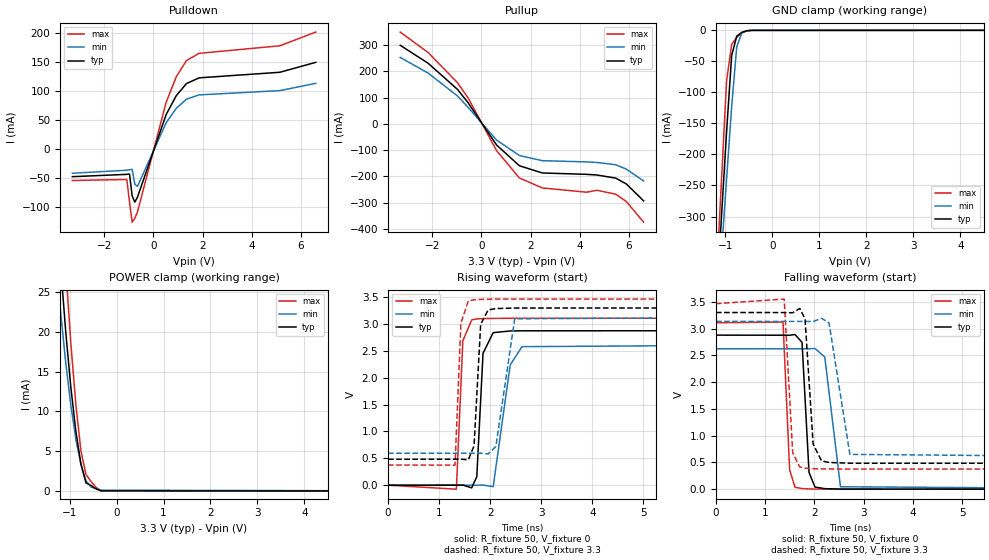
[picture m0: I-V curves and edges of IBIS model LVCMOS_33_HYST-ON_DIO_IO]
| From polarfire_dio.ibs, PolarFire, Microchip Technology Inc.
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|   Model LVCMOS_33_HYST-ON_DIO_IO
[Model]   LVCMOS_33_HYST-ON_DIO_IO
Model_type   I/O
Polarity   Non-Inverting
Enable   Active-High
Vinl =   0.8
Vinh =   2.0
Vmeas =   1.65
Cref =   0
Rref =   1M
|   typ   min   max
C_comp   5.210e-12   5.210e-12   5.520e-12
[Temperature Range]  25C   100C   -40C
[Voltage Range]  3.3   3.135   3.465
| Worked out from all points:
|   slope of the pulldown table from 0 to 0.495 V, typ, clamps not added: 8.62 ohm
|   slope of the pullup table from 0 to 0.495 V, typ, clamps not added: 7.48 ohm
|   GND clamp passes 1 mA (typ) near -0.56 V on its own axis
|   POWER clamp passes 1 mA (typ) near -0.65 V on its own axis
|   rising waveform, R_fixture 50, V_fixture 0: 20-80 % time 83.9ps typ, 115ps min, 62.2ps max; typ from 0 V to 2.88 V
|   rising waveform, R_fixture 50, V_fixture 3.3: 20-80 % time 82.6ps typ, 117ps min, 56.7ps max; typ from 0.483 V to 3.3 V
|   falling waveform, R_fixture 50, V_fixture 0: 20-80 % time 81.5ps typ, 112ps min, 62ps max; typ from 2.88 V to 0 V
|   falling waveform, R_fixture 50, V_fixture 3.3: 20-80 % time 106ps typ, 144ps min, 77.9ps max; typ from 3.3 V to 0.483 V
[GND Clamp]
| Voltage   I(typ)   I(min)   I(max)
-3.3V     -3.117A    -2.775A    -3.571A
-1.408V   -710mA     -709mA     -726.1mA
-1.083V   -300.1mA   -357.4mA   -241.4mA
-974.5mV  -163.4mA   -240mA     -81.84mA
-866.2mV  -40.57mA   -122.6mA   -22.65mA
-758mV    -9.307mA   -26.47mA   -11.46mA
-649.7mV  -3.312mA   -3.932mA   -4.242mA
-541.4mV  -660.8uA   -670.6uA   -884.8uA
-433.1mV  -42.49uA   -60.22uA   -57.85uA
6.6V      0A         0A         0A
[POWER Clamp]
| Voltage   I(typ)   I(min)   I(max)
-3.3V     276.9mA    224mA      333.7mA
-1.299V   37.66mA    29.74mA    51.11mA
-1.191V   28.36mA    22.59mA    39.07mA
-1.083V   20.16mA    16.24mA    28.21mA
-974.5mV  13.17mA    10.86mA    18.75mA
-866.2mV  7.523mA    6.52mA     10.91mA
-758mV    3.401mA    3.308mA    5.047mA
-649.7mV  998.1uA    1.291mA    2.065mA
-541.4mV  687.8uA    491.9uA    1.172mA
-433.1mV  241.5uA    288uA      436.1uA
-324.8mV  6.892uA    96.65uA    11.4uA
6.6V      0A         0A         0A
[Pullup]
| Voltage   I(typ)   I(min)   I(max)
-3.3V     299.9mA    253.5mA    350.3mA
-2.166V   231.4mA    194mA      272.3mA
-974.5mV  131.9mA    106.8mA    157.5mA
-541.4mV  80.8mA     63.2mA     99.39mA
618.8mV   -80.62mA   -61.84mA   -102.2mA
1.547V    -159.8mA   -120.7mA   -206.4mA
2.475V    -187.2mA   -140.4mA   -244.4mA
4.275V    -192.5mA   -145.1mA   -260.6mA
4.708V    -195.1mA   -147.2mA   -253.4mA
5.466V    -206.9mA   -156mA     -268.2mA
5.899V    -229.5mA   -172.8mA   -296.7mA
6.6V      -293.9mA   -217.9mA   -375.1mA
[Pulldown]
| Voltage   I(typ)   I(min)   I(max)
-3.3V     -47.51mA   -41.6mA    -54.13mA
-1.083V   -43.53mA   -36.42mA   -52.3mA
-974.5mV  -42.97mA   -35.55mA   -91.23mA
-866.2mV  -80.6mA    -34.99mA   -125.9mA
-758mV    -91.32mA   -60.63mA   -119.2mA
-649.7mV  -82.66mA   -64.24mA   -108.2mA
515.6mV   59.44mA    45.33mA    80.6mA
928.1mV   92.05mA    70.21mA    124.6mA
1.341V    112.8mA    85.88mA    152.5mA
1.856V    122.7mA    93.34mA    164.9mA
5.141V    132.3mA    100.7mA    177.9mA
6.6V      149.4mA    113.2mA    201.5mA
[Ramp]
dV/dt_r   1.72593/83.9062p  1.57401/0.115219n  1.8646/62.166p
dV/dt_f   1.69003/0.105543n  1.52447/0.143802n  1.85329/77.8518p
R_load = 50
[Rising Waveform]
R_fixture = 50
V_fixture = 0
V_fixture_min = 0
V_fixture_max = 0
| Time   V(typ)   V(min)   V(max)
0s        13.15nV    12.79nV    36.26nV
1.337ns   722.6uV    604.3uV    -73.68mV
1.464ns   3.294mV    661.7uV    2.689V
1.637ns   -49.29mV   739.8uV    3.077V
1.737ns   157.8mV    785uV      3.095V
1.859ns   2.455V     2.552mV    3.101V
2.058ns   2.84V      -27.13mV   3.105V
2.391ns   2.871V     2.238V     3.107V
2.621ns   2.874V     2.579V     3.108V
10ns      2.877V     2.623V     3.108V
[Rising Waveform]
R_fixture = 50
V_fixture = 3.3
V_fixture_min = 3.135
V_fixture_max = 3.465
| Time   V(typ)   V(min)   V(max)
0s        483.3mV    594.2mV    376.2mV
1.311ns   484.1mV    594.9mV    373.2mV
1.426ns   484.3mV    594.9mV    3.017V
1.571ns   472.5mV    595mV      3.431V
1.683ns   731.7mV    595.1mV    3.452V
1.813ns   2.995V     595.1mV    3.459V
1.96ns    3.263V     582.7mV    3.462V
2.111ns   3.288V     720.5mV    3.464V
2.479ns   3.298V     3.098V     3.464V
10ns      3.3V       3.135V     3.465V
[Falling Waveform]
R_fixture = 50
V_fixture = 0
V_fixture_min = 0
V_fixture_max = 0
| Time   V(typ)   V(min)   V(max)
0s        2.877V     2.623V     3.108V
1.362ns   2.876V     2.623V     3.122V
1.497ns   2.875V     2.623V     359.4mV
1.606ns   2.889V     2.623V     36.05mV
1.749ns   2.742V     2.623V     11.66mV
1.891ns   313mV      2.622V     4.403mV
2.011ns   39.38mV    2.628V     1.913mV
2.211ns   9.397mV    2.469V     852.3uV
2.53ns    1.347mV    45.15mV    817.4uV
10ns      130.8nV    260.3nV    53.88nV
[Falling Waveform]
R_fixture = 50
V_fixture = 3.3
V_fixture_min = 3.135
V_fixture_max = 3.465
| Time   V(typ)   V(min)   V(max)
0s        3.3V       3.135V     3.465V
1.386ns   3.299V     3.134V     3.551V
1.559ns   3.295V     3.134V     681.1mV
1.703ns   3.376V     3.134V     413.5mV
1.81ns    3.181V     3.134V     392.6mV
1.974ns   843.3mV    3.131V     381.8mV
2.146ns   527.7mV    3.192V     377.9mV
2.298ns   498.9mV    3.105V     376.8mV
2.721ns   484.6mV    649.5mV    376.3mV
10ns      483.3mV    594.2mV    376.2mV
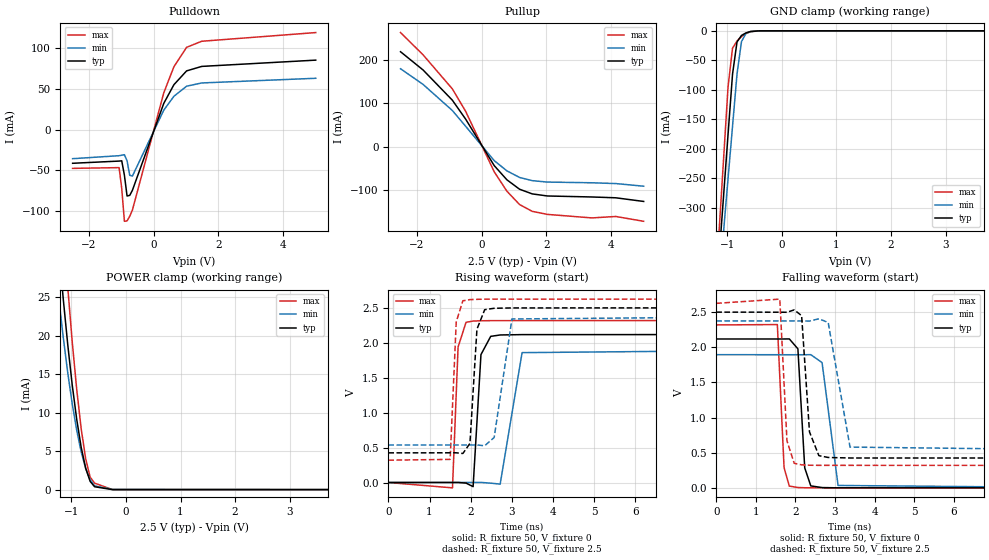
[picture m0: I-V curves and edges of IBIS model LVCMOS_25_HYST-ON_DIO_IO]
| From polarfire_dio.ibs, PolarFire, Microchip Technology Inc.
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|   Model LVCMOS_25_HYST-ON_DIO_IO
[Model]   LVCMOS_25_HYST-ON_DIO_IO
Model_type   I/O
Polarity   Non-Inverting
Enable   Active-High
Vinl =   0.7
Vinh =   1.7
Vmeas =   1.25
Cref =   0
Rref =   1M
|   typ   min   max
C_comp   5.210e-12   5.210e-12   5.520e-12
[Temperature Range]  25C   100C   -40C
[Voltage Range]  2.5   2.375   2.625
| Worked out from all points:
|   slope of the pulldown table from 0 to 0.375 V, typ, clamps not added: 9.99 ohm
|   slope of the pullup table from 0 to 0.375 V, typ, clamps not added: 9 ohm
|   GND clamp passes 1 mA (typ) near -0.56 V on its own axis
|   POWER clamp passes 1 mA (typ) near -0.65 V on its own axis
|   rising waveform, R_fixture 50, V_fixture 0: 20-80 % time 106ps typ, 156ps min, 74.6ps max; typ from 0 V to 2.12 V
|   rising waveform, R_fixture 50, V_fixture 2.5: 20-80 % time 120ps typ, 167ps min, 75.2ps max; typ from 0.425 V to 2.5 V
|   falling waveform, R_fixture 50, V_fixture 0: 20-80 % time 111ps typ, 160ps min, 76.3ps max; typ from 2.12 V to 0 V
|   falling waveform, R_fixture 50, V_fixture 2.5: 20-80 % time 142ps typ, 205ps min, 98.3ps max; typ from 2.5 V to 0.425 V
[GND Clamp]
| Voltage   I(typ)   I(min)   I(max)
-2.5V     -2.095A    -1.898A    -2.363A
-1.395V   -693.5mA   -694.8mA   -706.5mA
-1.066V   -279.4mA   -339.6mA   -216.9mA
-984.4mV  -175.8mA   -250.7mA   -94.98mA
-902.3mV  -73.48mA   -161.7mA   -29.46mA
-820.3mV  -18.91mA   -73.29mA   -17.3mA
-738.3mV  -7.793mA   -18.25mA   -9.861mA
-656.2mV  -3.56mA    -4.35mA    -4.565mA
-574.2mV  -1.196mA   -1.212mA   -1.543mA
-410.2mV  -21.32uA   -34.15uA   -26.17uA
5V        0A         0A         0A
[POWER Clamp]
| Voltage   I(typ)   I(min)   I(max)
-2.5V     165mA      130.6mA    202.6mA
-1.23V    31.26mA    24.82mA    42.73mA
-1.148V   24.72mA    19.74mA    34.16mA
-1.066V   18.82mA    15.17mA    26.29mA
-984.4mV  13.6mA     11.15mA    19.21mA
-902.3mV  9.142mA    7.719mA    13.04mA
-820.3mV  5.508mA    4.906mA    7.92mA
-738.3mV  2.791mA    2.758mA    4.018mA
-656.2mV  1.072mA    1.3mA      1.627mA
-574.2mV  370.7uA    485.9uA    841.5uA
-246.1mV  347.3nA    25.17uA    169.7nA
5V        0A         0A         0A
[Pullup]
| Voltage   I(typ)   I(min)   I(max)
-2.5V     219mA      179.8mA    263.1mA
-1.805V   177mA      143.8mA    211.9mA
-902.3mV  107.5mA    83.69mA    133.5mA
-492.2mV  63.92mA    47.44mA    81.89mA
390.6mV   -43.25mA   -31.76mA   -57.52mA
781.2mV   -75.89mA   -55.27mA   -102.1mA
1.172V    -97.57mA   -70.44mA   -132.8mA
1.562V    -108.3mA   -77.78mA   -148.5mA
2.031V    -113.1mA   -81.1mA    -155.5mA
3.402V    -115.4mA   -82.71mA   -163.6mA
4.141V    -117.3mA   -84.56mA   -160.3mA
5V        -125.7mA   -90.6mA    -171.4mA
[Pulldown]
| Voltage   I(typ)   I(min)   I(max)
-2.5V     -41.56mA   -35.9mA    -47.82mA
-1.066V   -38.84mA   -32.22mA   -46.91mA
-984.4mV  -38.52mA   -31.65mA   -72.62mA
-902.3mV  -56.23mA   -30.99mA   -113mA
-820.3mV  -81.83mA   -38.53mA   -112.5mA
-738.3mV  -81.09mA   -56.31mA   -106.9mA
-656.2mV  -74.9mA    -57.36mA   -99.27mA
312.5mV   32.26mA    23.92mA    45.26mA
625mV     55.23mA    40.94mA    77.37mA
1.016V    72.21mA    53.35mA    101.2mA
1.484V    77.74mA    57.36mA    108.7mA
5V        85.46mA    63.12mA    119.4mA
[Ramp]
dV/dt_r   1.27102/0.106207n  1.137/0.156314n  1.39063/74.598p
dV/dt_f   1.24529/0.142353n  1.10313/0.204769n  1.38324/98.2736p
R_load = 50
[Rising Waveform]
R_fixture = 50
V_fixture = 0
V_fixture_min = 0
V_fixture_max = 0
| Time   V(typ)   V(min)   V(max)
0s        3.055nV    9.243nV    3.186nV
1.559ns   476.4uV    514.2uV    -76.6mV
1.695ns   733.1uV    559uV      1.94V
1.888ns   -8.122mV   622.7uV    2.293V
2.06ns    -59.37mV   679.4uV    2.311V
2.251ns   1.831V     1.472mV    2.315V
2.488ns   2.092V     -9.262mV   2.317V
2.718ns   2.112V     -23.39mV   2.317V
3.251ns   2.117V     1.859V     2.318V
10ns      2.118V     1.895V     2.318V
[Rising Waveform]
R_fixture = 50
V_fixture = 2.5
V_fixture_min = 2.375
V_fixture_max = 2.625
| Time   V(typ)   V(min)   V(max)
0s        424.5mV    536.5mV    319.6mV
1.502ns   425.2mV    537mV      331mV
1.65ns    425.3mV    537.1mV    2.299V
1.811ns   415.2mV    537.2mV    2.601V
1.983ns   560.2mV    537.2mV    2.618V
2.153ns   2.194V     537.3mV    2.622V
2.342ns   2.474V     526.4mV    2.624V
2.572ns   2.494V     645.1mV    2.625V
3.004ns   2.499V     2.341V     2.625V
10ns      2.5V       2.375V     2.625V
[Falling Waveform]
R_fixture = 50
V_fixture = 0
V_fixture_min = 0
V_fixture_max = 0
| Time   V(typ)   V(min)   V(max)
0s        2.118V     1.895V     2.318V
1.543ns   2.118V     1.894V     2.323V
1.713ns   2.118V     1.894V     286.4mV
1.845ns   2.119V     1.894V     25.28mV
2.062ns   1.978V     1.894V     5.01mV
2.235ns   283.7mV    1.894V     1.642mV
2.388ns   28.06mV    1.895V     915uV
2.673ns   4.176mV    1.782V     880.8uV
3.077ns   393.1uV    34.37mV    832.2uV
10ns      212.4nV    437.4nV    100.6nV
[Falling Waveform]
R_fixture = 50
V_fixture = 2.5
V_fixture_min = 2.375
V_fixture_max = 2.625
| Time   V(typ)   V(min)   V(max)
0s        2.5V       2.375V     2.625V
1.605ns   2.499V     2.375V     2.685V
1.786ns   2.498V     2.375V     668mV
1.969ns   2.532V     2.375V     349.9mV
2.156ns   2.45V      2.374V     327.3mV
2.355ns   796.4mV    2.373V     321.9mV
2.592ns   458.2mV    2.405V     320.4mV
2.827ns   432.4mV    2.353V     320.4mV
3.379ns   424.9mV    580mV      320.3mV
10ns      424.5mV    536.5mV    319.6mV
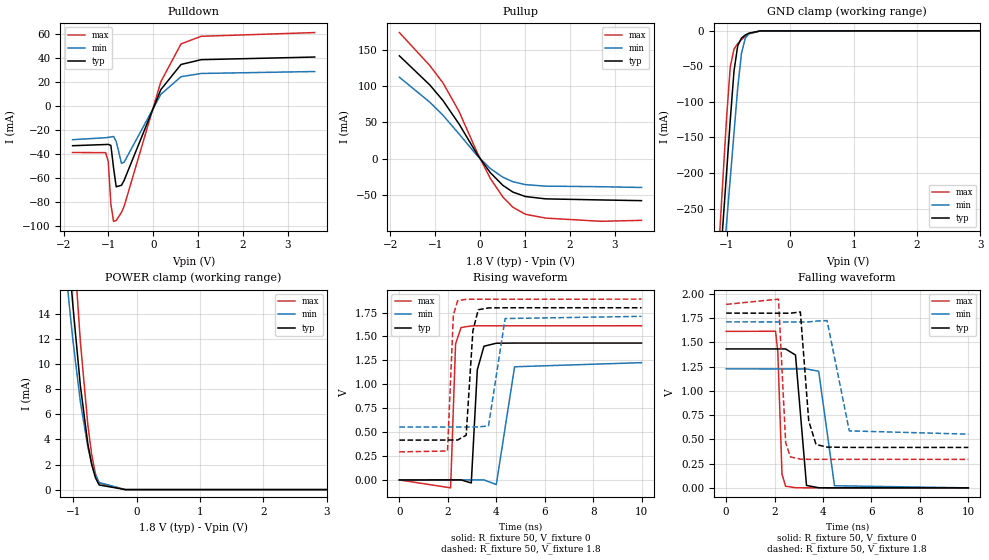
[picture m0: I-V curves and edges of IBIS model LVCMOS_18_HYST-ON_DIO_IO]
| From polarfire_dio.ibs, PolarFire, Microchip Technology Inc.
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|   Model LVCMOS_18_HYST-ON_DIO_IO
[Model]   LVCMOS_18_HYST-ON_DIO_IO
Model_type   I/O
Polarity   Non-Inverting
Enable   Active-High
Vinl =   0.63
Vinh =   1.17
Vmeas =   0.9
Cref =   0
Rref =   1M
|   typ   min   max
C_comp   5.210e-12   5.210e-12   5.520e-12
[Temperature Range]  25C   100C   -40C
[Voltage Range]  1.8   1.71   1.89
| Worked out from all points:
|   slope of the pulldown table from 0 to 0.27 V, typ, clamps not added: 13.4 ohm
|   slope of the pullup table from 0 to 0.27 V, typ, clamps not added: 12.3 ohm
|   GND clamp passes 1 mA (typ) near -0.56 V on its own axis
|   POWER clamp passes 1 mA (typ) near -0.65 V on its own axis
|   rising waveform, R_fixture 50, V_fixture 0: 20-80 % time 168ps typ, 272ps min, 104ps max; typ from 0 V to 1.43 V
|   rising waveform, R_fixture 50, V_fixture 1.8: 20-80 % time 204ps typ, 277ps min, 126ps max; typ from 0.416 V to 1.8 V
|   falling waveform, R_fixture 50, V_fixture 0: 20-80 % time 188ps typ, 262ps min, 119ps max; typ from 1.43 V to 0 V
|   falling waveform, R_fixture 50, V_fixture 1.8: 20-80 % time 246ps typ, 393ps min, 155ps max; typ from 1.8 V to 0.416 V
[GND Clamp]
| Voltage   I(typ)   I(min)   I(max)
-1.8V     -1.205A    -1.134A    -1.312A
-1.122V   -349.8mA   -400mA     -300.1mA
-1.063V   -275.3mA   -336.1mA   -212mA
-1.004V   -200.7mA   -272.1mA   -124mA
-945mV    -126mA     -208mA     -50.93mA
-885.9mV  -56.73mA   -143.9mA   -25.77mA
-826.9mV  -20.87mA   -80mA      -17.98mA
-767.8mV  -10.21mA   -31.7mA    -12.3mA
-708.7mV  -5.982mA   -10.49mA   -7.692mA
-649.7mV  -3.311mA   -3.931mA   -4.24mA
-472.5mV  -129.2uA   -153.5uA   -189.6uA
3.6V      0A         0A         0A
[POWER Clamp]
| Voltage   I(typ)   I(min)   I(max)
-1.8V     86.23mA    65.8mA     111.2mA
-1.181V   27.05mA    21.5mA     37.2mA
-1.122V   22.57mA    18.03mA    31.3mA
-1.063V   18.44mA    14.83mA    25.76mA
-1.004V   14.67mA    11.92mA    20.64mA
-885.9mV  8.285mA    7.004mA    11.79mA
-767.8mV  3.63mA     3.384mA    5.147mA
-708.7mV  2.037mA    2.095mA    2.833mA
-649.7mV  965.6uA    1.163mA    1.28mA
-590.6mV  371.5uA    565.4uA    529.2uA
-177.2mV  893pA      1.382uA    111.2nA
3.6V      0A         0A         0A
[Pullup]
| Voltage   I(typ)   I(min)   I(max)
-1.8V     141.7mA    112.3mA    173.7mA
-1.122V   101.7mA    77.94mA    128.4mA
-826.9mV  80.12mA    59.94mA    104.4mA
-472.5mV  48.24mA    34.49mA    65.57mA
-59.06mV  5.582mA    3.989mA    7.857mA
225mV     -18.79mA   -13.15mA   -26.66mA
506.2mV   -36.4mA    -25.27mA   -52.38mA
731.2mV   -45.74mA   -31.52mA   -66.56mA
1.012V    -51.87mA   -35.5mA    -76.31mA
1.462V    -55.09mA   -37.58mA   -81.53mA
2.686V    -56.56mA   -38.35mA   -85.94mA
3.6V      -57.53mA   -39.42mA   -84.65mA
[Pulldown]
| Voltage   I(typ)   I(min)   I(max)
-1.8V     -33.14mA   -28.12mA   -38.79mA
-1.063V   -32.14mA   -26.5mA    -38.91mA
-1.004V   -32.03mA   -26.19mA   -46.39mA
-945mV    -32.91mA   -25.84mA   -81.99mA
-885.9mV  -51.56mA   -25.43mA   -96.1mA
-826.9mV  -67.35mA   -29.57mA   -95.49mA
-708.7mV  -66.09mA   -47.84mA   -88.63mA
-649.7mV  -61.97mA   -46.84mA   -83.61mA
168.8mV   13.57mA    9.638mA    20.15mA
618.8mV   34.53mA    24.36mA    51.68mA
1.069V    38.53mA    27.03mA    58mA
3.6V      40.73mA    28.66mA    61.11mA
[Ramp]
dV/dt_r   0.85864/0.167888n  0.735429/0.272041n  0.966984/0.10411n
dV/dt_f   0.830138/0.245894n  0.694162/0.392686n  0.957958/0.154706n
R_load = 50
[Rising Waveform]
R_fixture = 50
V_fixture = 0
V_fixture_min = 0
V_fixture_max = 0
| Time   V(typ)   V(min)   V(max)
0s        2.576nV    10nV       1.786nV
2.116ns   391.7uV    616.9uV    -82.64mV
2.321ns   429.7uV    676.7uV    1.422V
2.547ns   412.1uV    742.6uV    1.593V
2.97ns    -31.45mV   865.9uV    1.61V
3.219ns   1.152V     938.5uV    1.611V
3.495ns   1.398V     408.2uV    1.611V
4.003ns   1.429V     -47.81mV   1.611V
4.759ns   1.431V     1.183V     1.611V
10ns      1.431V     1.226V     1.612V
[Rising Waveform]
R_fixture = 50
V_fixture = 1.8
V_fixture_min = 1.71
V_fixture_max = 1.89
| Time   V(typ)   V(min)   V(max)
0s        416.4mV    553.1mV    293.4mV
1.989ns   417.2mV    553.4mV    302.4mV
2.23ns    417.3mV    553.4mV    1.722V
2.404ns   417.5mV    553.4mV    1.873V
2.758ns   466.8mV    553.5mV    1.888V
3.036ns   1.558V     553.5mV    1.889V
3.257ns   1.779V     553.7mV    1.889V
3.682ns   1.798V     565.7mV    1.889V
4.367ns   1.8V       1.687V     1.889V
10ns      1.8V       1.71V      1.89V
[Falling Waveform]
R_fixture = 50
V_fixture = 0
V_fixture_min = 0
V_fixture_max = 0
| Time   V(typ)   V(min)   V(max)
0s        1.431V     1.226V     1.612V
2.039ns   1.431V     1.225V     1.613V
2.133ns   1.431V     1.225V     1.397V
2.305ns   1.431V     1.225V     143.2mV
2.451ns   1.431V     1.225V     17.09mV
2.862ns   1.368V     1.225V     1.249mV
3.317ns   24.81mV    1.225V     426.4uV
3.82ns    1.254mV    1.201V     394.3uV
4.473ns   244.2uV    21.79mV    352.7uV
10ns      358nV      485.8nV    272.1nV
[Falling Waveform]
R_fixture = 50
V_fixture = 1.8
V_fixture_min = 1.71
V_fixture_max = 1.89
| Time   V(typ)   V(min)   V(max)
0s        1.8V       1.71V      1.89V
2.16ns    1.799V     1.709V     1.944V
2.457ns   1.799V     1.709V     464.3mV
2.654ns   1.799V     1.709V     319.1mV
3.064ns   1.812V     1.709V     295.6mV
3.409ns   689.6mV    1.709V     294mV
3.71ns    446.7mV    1.718V     294mV
4.166ns   419.8mV    1.723V     293.9mV
5.085ns   416.7mV    587mV      293.9mV
10ns      416.4mV    553.1mV    293.4mV
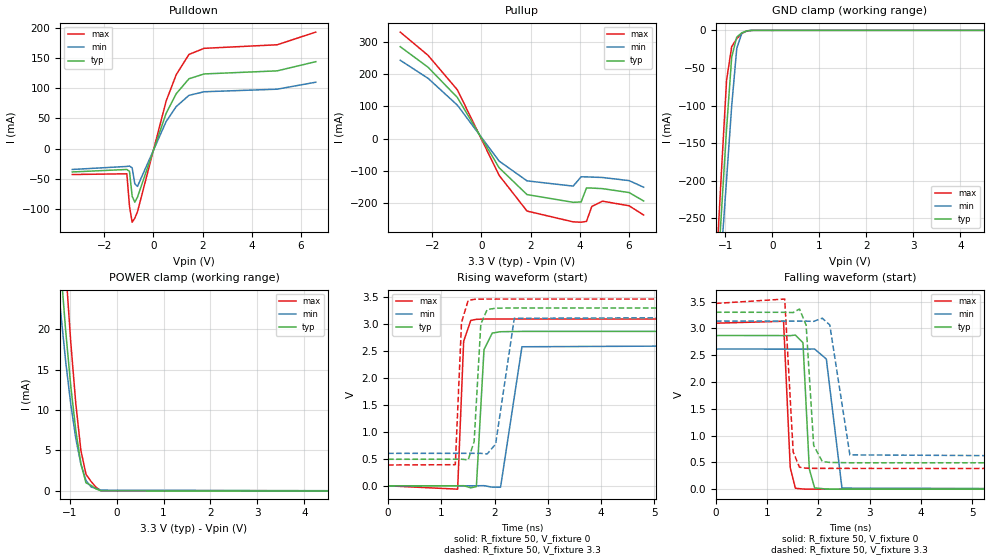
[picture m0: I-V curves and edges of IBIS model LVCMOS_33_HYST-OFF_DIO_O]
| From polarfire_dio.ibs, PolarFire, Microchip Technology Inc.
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|   Model LVCMOS_33_HYST-OFF_DIO_O
[Model]   LVCMOS_33_HYST-OFF_DIO_O
Model_type   Output
Polarity   Non-Inverting
Enable   Active-High
Vmeas =   1.65
Cref =   0
Rref =   1M
|   typ   min   max
C_comp   5.210e-12   5.210e-12   5.520e-12
[Temperature Range]  25C   100C   -40C
[Voltage Range]  3.3   3.135   3.465
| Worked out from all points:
|   slope of the pulldown table from 0 to 0.495 V, typ, clamps not added: 8.78 ohm
|   slope of the pullup table from 0 to 0.495 V, typ, clamps not added: 7.68 ohm
|   GND clamp passes 1 mA (typ) near -0.56 V on its own axis
|   POWER clamp passes 1 mA (typ) near -0.65 V on its own axis
|   rising waveform, R_fixture 50, V_fixture 0: 20-80 % time 80.9ps typ, 111ps min, 60ps max; typ from 0 V to 2.87 V
|   rising waveform, R_fixture 50, V_fixture 3.3: 20-80 % time 86.3ps typ, 122ps min, 58.7ps max; typ from 0.492 V to 3.3 V
|   falling waveform, R_fixture 50, V_fixture 0: 20-80 % time 76.8ps typ, 101ps min, 59.3ps max; typ from 2.87 V to 0 V
|   falling waveform, R_fixture 50, V_fixture 3.3: 20-80 % time 98.9ps typ, 134ps min, 74.1ps max; typ from 3.3 V to 0.492 V
[GND Clamp]
| Voltage   I(typ)   I(min)   I(max)
-3.3V     -2.496A    -2.286A    -2.76A
-1.191V   -350.6mA   -391.8mA   -312.3mA
-1.083V   -240.9mA   -295mA     -187.1mA
-974.5mV  -131mA     -198.1mA   -66.4mA
-866.2mV  -35.74mA   -101.1mA   -21.82mA
-758mV    -9.042mA   -24.11mA   -11.13mA
-649.7mV  -3.236mA   -3.831mA   -4.137mA
-541.4mV  -641.9uA   -649.7uA   -862.7uA
-433.1mV  -39.78uA   -56.66uA   -54.99uA
6.6V      0A         0A         0A
[POWER Clamp]
| Voltage   I(typ)   I(min)   I(max)
-3.3V     267.5mA    217.4mA    320.4mA
-1.299V   36.87mA    29.24mA    49.76mA
-1.191V   27.83mA    22.24mA    38.13mA
-1.083V   19.83mA    16.03mA    27.61mA
-974.5mV  12.99mA    10.74mA    18.4mA
-866.2mV  7.439mA    6.459mA    10.74mA
-758mV    3.374mA    3.284mA    4.987mA
-649.7mV  993.1uA    1.284mA    2.053mA
-541.4mV  687.6uA    490.7uA    1.166mA
-433.1mV  238.1uA    287.8uA    429.7uA
-324.8mV  6.781uA    96.53uA    11.45uA
6.6V      0A         0A         0A
[Pullup]
| Voltage   I(typ)   I(min)   I(max)
-3.3V     284.3mA    242.4mA    329.4mA
-2.166V   220.6mA    186.4mA    257.3mA
-974.5mV  127.1mA    103.5mA    150.7mA
721.9mV   -89.81mA   -69.17mA   -113.3mA
1.856V    -172.7mA   -130.3mA   -223.6mA
3.733V    -196.6mA   -146.5mA   -257mA
4.058V    -195.4mA   -117.7mA   -258mA
4.275V    -152.1mA   -118mA     -255.6mA
4.491V    -152.6mA   -118.6mA   -209.5mA
4.924V    -154.3mA   -119.9mA   -193.1mA
6.007V    -166.4mA   -129.5mA   -207.2mA
6.6V      -192.5mA   -150mA     -235.9mA
[Pulldown]
| Voltage   I(typ)   I(min)   I(max)
-3.3V     -38.79mA   -34.69mA   -43.07mA
-1.083V   -34.72mA   -29.68mA   -41.85mA
-974.5mV  -37.99mA   -29.03mA   -95.72mA
-866.2mV  -79.08mA   -31.94mA   -122mA
-758mV    -88.84mA   -58.53mA   -115.2mA
-649.7mV  -80.51mA   -62.77mA   -104.7mA
515.6mV   58.35mA    44.7mA     78.62mA
928.1mV   90.9mA     69.54mA    122.5mA
1.444V    115.5mA    88.04mA    155.8mA
2.062V    123.5mA    94.01mA    165.9mA
5.032V    128.6mA    98.25mA    171.8mA
6.6V      143.8mA    109.8mA    192.8mA
[Ramp]
dV/dt_r   1.71943/80.9268p  1.56835/0.110667n  1.85733/59.955p
dV/dt_f   1.68455/98.9451p  1.51988/0.134109n  1.84694/74.1429p
R_load = 50
[Rising Waveform]
R_fixture = 50
V_fixture = 0
V_fixture_min = 0
V_fixture_max = 0
| Time   V(typ)   V(min)   V(max)
0s        12.92nV    12.54nV    35.54nV
1.307ns   827.3uV    645.9uV    -62.18mV
1.42ns    2.54mV     701.8uV    2.682V
1.554ns   -37.98mV   768uV      3.069V
1.659ns   -14.36mV   819.9uV    3.089V
1.802ns   2.527V     2.682mV    3.094V
1.956ns   2.833V     -24.83mV   3.095V
2.113ns   2.859V     -26.26mV   3.095V
2.515ns   2.865V     2.58V      3.095V
10ns      2.866V     2.614V     3.096V
[Rising Waveform]
R_fixture = 50
V_fixture = 3.3
V_fixture_min = 3.135
V_fixture_max = 3.465
| Time   V(typ)   V(min)   V(max)
0s        492.4mV    601.9mV    386.8mV
1.263ns   493.1mV    602.6mV    391.9mV
1.38ns    493.3mV    602.6mV    3.031V
1.505ns   481.7mV    602.7mV    3.441V
1.617ns   822.1mV    602.8mV    3.46V
1.742ns   3V         602.7mV    3.464V
1.861ns   3.269V     590.2mV    3.465V
2.02ns    3.295V     773.3mV    3.465V
2.371ns   3.3V       3.108V     3.465V
10ns      3.3V       3.135V     3.465V
[Falling Waveform]
R_fixture = 50
V_fixture = 0
V_fixture_min = 0
V_fixture_max = 0
| Time   V(typ)   V(min)   V(max)
0s        2.866V     2.614V     3.096V
1.318ns   2.865V     2.613V     3.132V
1.449ns   2.864V     2.613V     398.5mV
1.549ns   2.874V     2.613V     16.9mV
1.697ns   2.732V     2.613V     2.398mV
1.821ns   373.8mV    2.613V     608.7uV
1.924ns   24.47mV    2.614V     212.9uV
2.153ns   1.854mV    2.428V     -25.88uV
2.458ns   372uV      19.15mV    -24.88uV
10ns      10.43nV    38.87nV    39.93nV
[Falling Waveform]
R_fixture = 50
V_fixture = 3.3
V_fixture_min = 3.135
V_fixture_max = 3.465
| Time   V(typ)   V(min)   V(max)
0s        3.3V       3.135V     3.465V
1.341ns   3.299V     3.135V     3.546V
1.506ns   3.294V     3.134V     694.2mV
1.629ns   3.361V     3.134V     409mV
1.759ns   3.059V     3.134V     391.7mV
1.906ns   817mV      3.13V      387.5mV
2.074ns   515.3mV    3.189V     387.3mV
2.22ns    498.3mV    3.063V     387.3mV
2.612ns   492.5mV    639.6mV    387.3mV
10ns      492.4mV    601.9mV    386.8mV
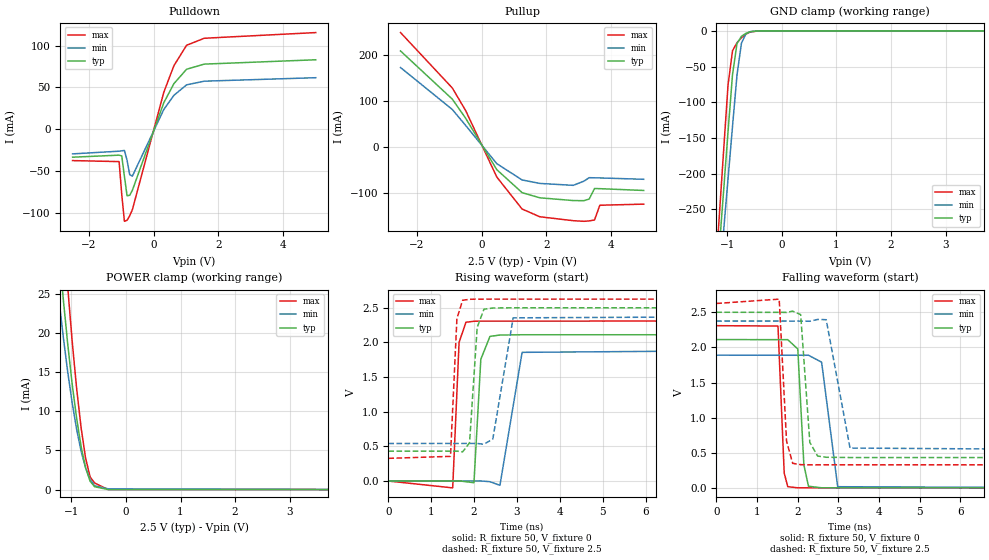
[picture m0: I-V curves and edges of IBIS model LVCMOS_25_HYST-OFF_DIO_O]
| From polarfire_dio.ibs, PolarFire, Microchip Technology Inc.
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|   Model LVCMOS_25_HYST-OFF_DIO_O
[Model]   LVCMOS_25_HYST-OFF_DIO_O
Model_type   Output
Polarity   Non-Inverting
Enable   Active-High
Vmeas =   1.25
Cref =   0
Rref =   1M
|   typ   min   max
C_comp   5.210e-12   5.210e-12   5.520e-12
[Temperature Range]  25C   100C   -40C
[Voltage Range]  2.5   2.375   2.625
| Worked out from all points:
|   slope of the pulldown table from 0 to 0.375 V, typ, clamps not added: 10.2 ohm
|   slope of the pullup table from 0 to 0.375 V, typ, clamps not added: 9.19 ohm
|   GND clamp passes 1 mA (typ) near -0.56 V on its own axis
|   POWER clamp passes 1 mA (typ) near -0.65 V on its own axis
|   rising waveform, R_fixture 50, V_fixture 0: 20-80 % time 102ps typ, 150ps min, 71.4ps max; typ from 0 V to 2.11 V
|   rising waveform, R_fixture 50, V_fixture 2.5: 20-80 % time 122ps typ, 173ps min, 79.5ps max; typ from 0.431 V to 2.5 V
|   falling waveform, R_fixture 50, V_fixture 0: 20-80 % time 100ps typ, 140ps min, 71.1ps max; typ from 2.11 V to 0 V
|   falling waveform, R_fixture 50, V_fixture 2.5: 20-80 % time 132ps typ, 191ps min, 90.9ps max; typ from 2.5 V to 0.431 V
[GND Clamp]
| Voltage   I(typ)   I(min)   I(max)
-2.5V     -1.679A    -1.564A    -1.828A
-1.477V   -639.7mA   -646.8mA   -642.5mA
-1.148V   -307.4mA   -353.7mA   -263mA
-1.066V   -224.2mA   -280.3mA   -168.1mA
-984.4mV  -141mA     -206.9mA   -75.61mA
-902.3mV  -60.93mA   -133.4mA   -27.8mA
-820.3mV  -17.83mA   -61.68mA   -16.76mA
-738.3mV  -7.59mA    -17.01mA   -9.586mA
-656.2mV  -3.478mA   -4.235mA   -4.452mA
-574.2mV  -1.166mA   -1.18mA    -1.507mA
-410.2mV  -20.08uA   -32.05uA   -24.59uA
5V        0A         0A         0A
[POWER Clamp]
| Voltage   I(typ)   I(min)   I(max)
-2.5V     160.3mA    127.5mA    195.9mA
-1.23V    30.66mA    24.43mA    41.69mA
-1.148V   24.29mA    19.45mA    33.39mA
-1.066V   18.52mA    14.97mA    25.75mA
-984.4mV  13.41mA    11.03mA    18.86mA
-902.3mV  9.033mA    7.644mA    12.83mA
-820.3mV  5.454mA    4.866mA    7.812mA
-738.3mV  2.77mA     2.739mA    3.975mA
-656.2mV  1.066mA    1.294mA    1.617mA
-574.2mV  370.6uA    484uA      841.3uA
-328.1mV  7.68uA     101.4uA    7.539uA
5V        0A         0A         0A
[Pullup]
| Voltage   I(typ)   I(min)   I(max)
-2.5V     209mA      172.9mA    249.1mA
-902.3mV  104mA      81.45mA    128.3mA
-492.2mV  62.44mA    46.82mA    79.22mA
468.8mV   -49.63mA   -36.58mA   -65.69mA
1.25V     -99.75mA   -72.09mA   -135.5mA
1.797V    -111mA     -79.67mA   -152.3mA
2.828V    -117mA     -83.84mA   -160.9mA
3.156V    -117.3mA   -74.75mA   -162.2mA
3.32V     -113.7mA   -67.14mA   -161.3mA
3.484V    -90.73mA   -67.41mA   -159.3mA
3.648V    -91.11mA   -67.68mA   -127.2mA
5V        -94.99mA   -70.64mA   -124.8mA
[Pulldown]
| Voltage   I(typ)   I(min)   I(max)
-2.5V     -33.46mA   -29.51mA   -37.53mA
-1.066V   -31.03mA   -26.28mA   -38.76mA
-984.4mV  -31.94mA   -25.85mA   -77.86mA
-902.3mV  -56.28mA   -25.39mA   -110.2mA
-820.3mV  -79.63mA   -37.22mA   -109mA
-738.3mV  -79.02mA   -54.45mA   -103.6mA
-656.2mV  -73.07mA   -56.09mA   -96.24mA
312.5mV   31.72mA    23.62mA    44.19mA
625mV     54.58mA    40.59mA    76.11mA
1.016V    71.81mA    53.14mA    100.5mA
1.562V    77.94mA    57.52mA    108.9mA
5V        83.13mA    61.67mA    115.7mA
[Ramp]
dV/dt_r   1.26639/0.101977n  1.13317/0.150236n  1.38531/71.4107p
dV/dt_f   1.24141/0.131969n  1.10005/0.191455n  1.37859/90.8551p
R_load = 50
[Rising Waveform]
R_fixture = 50
V_fixture = 0
V_fixture_min = 0
V_fixture_max = 0
| Time   V(typ)   V(min)   V(max)
0s        3.015nV    9.048nV    3.118nV
1.501ns   666uV      571.9uV    -98.44mV
1.65ns    2.358mV    628.7uV    2.002V
1.81ns    -9.896mV   689.7uV    2.291V
1.997ns   -23.95mV   760.9uV    2.306V
2.157ns   1.757V     1.214mV    2.308V
2.37ns    2.087V     -9.475mV   2.308V
2.603ns   2.107V     -61.86mV   2.308V
3.12ns    2.111V     1.857V     2.308V
10ns      2.111V     1.889V     2.309V
[Rising Waveform]
R_fixture = 50
V_fixture = 2.5
V_fixture_min = 2.375
V_fixture_max = 2.625
| Time   V(typ)   V(min)   V(max)
0s        431mV      541.6mV    327.3mV
1.449ns   431.8mV    542.2mV    356.2mV
1.599ns   431.9mV    542.3mV    2.344V
1.732ns   420.7mV    542.4mV    2.608V
1.894ns   551.6mV    542.5mV    2.623V
2.072ns   2.216V     542.5mV    2.624V
2.229ns   2.479V     530.9mV    2.625V
2.437ns   2.497V     606.6mV    2.625V
2.912ns   2.5V       2.355V     2.625V
10ns      2.5V       2.375V     2.625V
[Falling Waveform]
R_fixture = 50
V_fixture = 0
V_fixture_min = 0
V_fixture_max = 0
| Time   V(typ)   V(min)   V(max)
0s        2.111V     1.889V     2.309V
1.517ns   2.11V      1.888V     2.304V
1.67ns    2.11V      1.888V     211.3mV
1.757ns   2.11V      1.888V     16.77mV
2.004ns   1.977V     1.888V     958.2uV
2.154ns   326mV      1.888V     152.5uV
2.267ns   22.81mV    1.888V     128.1uV
2.59ns    994.8uV    1.789V     122.8uV
2.985ns   31.17uV    16.38mV    116.2uV
10ns      15.04nV    -20.4nV    37.17nV
[Falling Waveform]
R_fixture = 50
V_fixture = 2.5
V_fixture_min = 2.375
V_fixture_max = 2.625
| Time   V(typ)   V(min)   V(max)
0s        2.5V       2.375V     2.625V
1.547ns   2.499V     2.375V     2.687V
1.727ns   2.498V     2.375V     667mV
1.878ns   2.516V     2.374V     349.4mV
2.075ns   2.466V     2.374V     330.4mV
2.3ns     646.9mV    2.372V     328.2mV
2.492ns   452.9mV    2.398V     328.1mV
2.703ns   435.7mV    2.394V     328.1mV
3.288ns   431.7mV    566.7mV    328.1mV
10ns      431mV      541.6mV    327.4mV
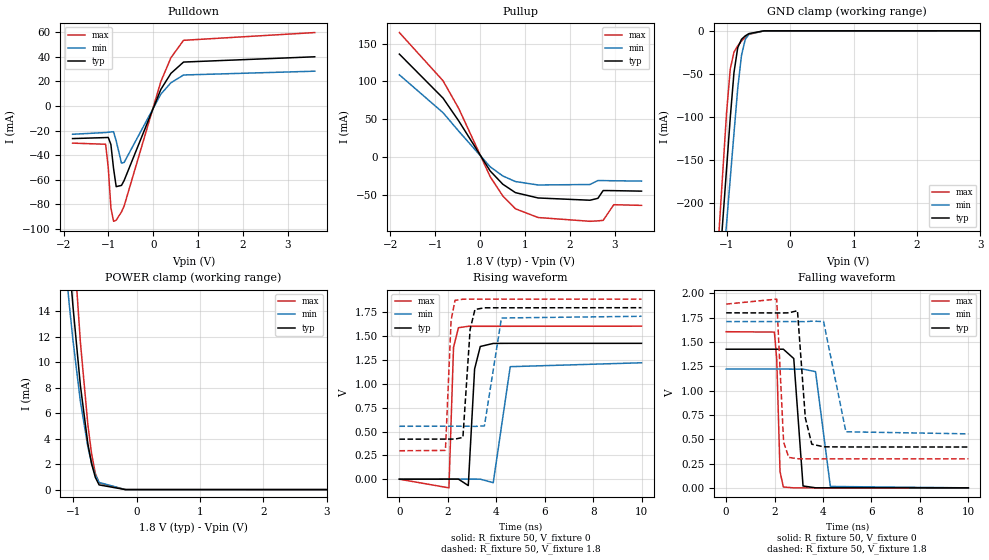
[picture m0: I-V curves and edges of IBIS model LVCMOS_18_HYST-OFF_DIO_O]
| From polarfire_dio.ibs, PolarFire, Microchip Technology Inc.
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|   Model LVCMOS_18_HYST-OFF_DIO_O
[Model]   LVCMOS_18_HYST-OFF_DIO_O
Model_type   Output
Polarity   Non-Inverting
Enable   Active-High
Vmeas =   0.9
Cref =   0
Rref =   1M
|   typ   min   max
C_comp   5.210e-12   5.210e-12   5.520e-12
[Temperature Range]  25C   100C   -40C
[Voltage Range]  1.8   1.71   1.89
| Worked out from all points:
|   slope of the pulldown table from 0 to 0.27 V, typ, clamps not added: 13.6 ohm
|   slope of the pullup table from 0 to 0.27 V, typ, clamps not added: 12.4 ohm
|   GND clamp passes 1 mA (typ) near -0.56 V on its own axis
|   POWER clamp passes 1 mA (typ) near -0.65 V on its own axis
|   rising waveform, R_fixture 50, V_fixture 0: 20-80 % time 158ps typ, 259ps min, 99.8ps max; typ from 0 V to 1.43 V
|   rising waveform, R_fixture 50, V_fixture 1.8: 20-80 % time 201ps typ, 263ps min, 128ps max; typ from 0.42 V to 1.8 V
|   falling waveform, R_fixture 50, V_fixture 0: 20-80 % time 169ps typ, 240ps min, 107ps max; typ from 1.43 V to 0 V
|   falling waveform, R_fixture 50, V_fixture 1.8: 20-80 % time 232ps typ, 367ps min, 142ps max; typ from 1.8 V to 0.42 V
[GND Clamp]
| Voltage   I(typ)   I(min)   I(max)
-1.8V     -967.4mA   -936mA     -1.017A
-1.122V   -280.8mA   -330.2mA   -232.6mA
-1.063V   -220.9mA   -277.4mA   -164.3mA
-1.004V   -161mA     -224.5mA   -96.19mA
-945mV    -101.1mA   -171.6mA   -44.3mA
-885.9mV  -48.29mA   -118.7mA   -24.65mA
-826.9mV  -19.53mA   -66.85mA   -17.42mA
-767.8mV  -9.896mA   -28.51mA   -11.95mA
-708.7mV  -5.838mA   -10.03mA   -7.488mA
-649.7mV  -3.236mA   -3.831mA   -4.137mA
-413.4mV  -21.99uA   -34.81uA   -27.67uA
3.6V      0A         0A         0A
[POWER Clamp]
| Voltage   I(typ)   I(min)   I(max)
-1.8V     84.18mA    64.55mA    108.3mA
-1.181V   26.56mA    21.18mA    36.35mA
-1.122V   22.19mA    17.78mA    30.61mA
-1.063V   18.15mA    14.64mA    25.24mA
-1.004V   14.46mA    11.78mA    20.25mA
-885.9mV  8.189mA    6.938mA    11.61mA
-767.8mV  3.599mA    3.36mA     5.087mA
-708.7mV  2.023mA    2.083mA    2.807mA
-649.7mV  960.8uA    1.157mA    1.272mA
-590.6mV  370.1uA    563.2uA    527.4uA
-177.2mV  3.647uA    1.451uA    394.3nA
3.6V      0A         0A         0A
[Pullup]
| Voltage   I(typ)   I(min)   I(max)
-1.8V     136.1mA    108.7mA    164.6mA
-826.9mV  77.93mA    58.62mA    100.9mA
-472.5mV  47.38mA    33.92mA    63.75mA
225mV     -18.49mA   -13mA      -26.05mA
506.2mV   -36mA      -25.08mA   -51.52mA
787.5mV   -47.14mA   -32.49mA   -68.52mA
1.294V    -54.22mA   -37.03mA   -80.09mA
2.45V     -57.21mA   -36.41mA   -85.08mA
2.627V    -54.71mA   -31.15mA   -84.51mA
2.745V    -44.38mA   -31.25mA   -83.85mA
2.981V    -44.54mA   -31.45mA   -63.12mA
3.6V      -45.17mA   -31.9mA    -64mA
[Pulldown]
| Voltage   I(typ)   I(min)   I(max)
-1.8V     -26.54mA   -23.04mA   -30.22mA
-1.063V   -25.73mA   -21.64mA   -31.16mA
-1.004V   -25.63mA   -21.4mA    -50.06mA
-945mV    -31.3mA    -21.13mA   -82.69mA
-885.9mV  -50.84mA   -20.98mA   -93.72mA
-826.9mV  -65.57mA   -28.4mA    -92.78mA
-708.7mV  -64.56mA   -46.5mA    -86.11mA
-649.7mV  -60.59mA   -45.89mA   -81.3mA
168.8mV   13.38mA    9.543mA    19.74mA
393.7mV   26.41mA    18.78mA    39.13mA
675mV     35.6mA     25.1mA     53.26mA
3.6V      39.88mA    28.18mA    59.55mA
[Ramp]
dV/dt_r   0.855785/0.15804n  0.733365/0.25905n  0.963449/99.7524p
dV/dt_f   0.827915/0.232068n  0.692754/0.367123n  0.954922/0.142147n
R_load = 50
[Rising Waveform]
R_fixture = 50
V_fixture = 0
V_fixture_min = 0
V_fixture_max = 0
| Time   V(typ)   V(min)   V(max)
0s        2.514nV    9.756nV    1.765nV
2.047ns   645uV      601.1uV    -90.97mV
2.237ns   704.9uV    656.9uV    1.386V
2.44ns    633.7uV    716.5uV    1.59V
2.846ns   -67.05mV   835.7uV    1.605V
3.107ns   1.157V     982.8uV    1.605V
3.342ns   1.393V     275.1uV    1.605V
3.877ns   1.425V     -36.48mV   1.605V
4.578ns   1.426V     1.181V     1.605V
10ns      1.426V     1.222V     1.606V
[Rising Waveform]
R_fixture = 50
V_fixture = 1.8
V_fixture_min = 1.71
V_fixture_max = 1.89
| Time   V(typ)   V(min)   V(max)
0s        420.1mV    555.4mV    298.5mV
1.902ns   420.8mV    555.9mV    301.9mV
2.137ns   420.9mV    555.9mV    1.669V
2.299ns   420.8mV    556mV      1.877V
2.624ns   438.7mV    556.1mV    1.889V
2.922ns   1.572V     556.1mV    1.89V
3.121ns   1.781V     554.2mV    1.89V
3.512ns   1.799V     559.1mV    1.89V
4.216ns   1.799V     1.692V     1.89V
10ns      1.8V       1.71V      1.89V
[Falling Waveform]
R_fixture = 50
V_fixture = 0
V_fixture_min = 0
V_fixture_max = 0
| Time   V(typ)   V(min)   V(max)
0s        1.426V     1.222V     1.606V
1.991ns   1.426V     1.222V     1.602V
2.088ns   1.426V     1.222V     1.32V
2.224ns   1.426V     1.222V     166.9mV
2.361ns   1.426V     1.222V     8.919mV
2.791ns   1.33V      1.221V     205.4uV
3.174ns   19.47mV    1.221V     54.04uV
3.691ns   574.8uV    1.195V     49.94uV
4.302ns   17.09uV    14.39mV    45.11uV
10ns      9.442nV    34.97nV    6.699nV
[Falling Waveform]
R_fixture = 50
V_fixture = 1.8
V_fixture_min = 1.71
V_fixture_max = 1.89
| Time   V(typ)   V(min)   V(max)
0s        1.8V       1.71V      1.89V
2.086ns   1.799V     1.71V      1.941V
2.372ns   1.799V     1.71V      469.9mV
2.583ns   1.8V       1.71V      313.5mV
2.944ns   1.822V     1.71V      299.6mV
3.268ns   719.8mV    1.709V     298.7mV
3.536ns   449.2mV    1.714V     298.7mV
4.023ns   422.3mV    1.711V     298.7mV
4.944ns   420.5mV    576.7mV    298.6mV
10ns      420.1mV    555.4mV    298.5mV
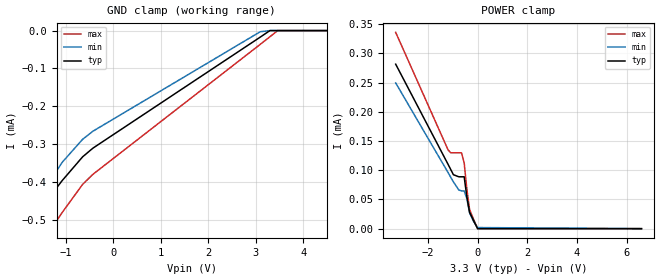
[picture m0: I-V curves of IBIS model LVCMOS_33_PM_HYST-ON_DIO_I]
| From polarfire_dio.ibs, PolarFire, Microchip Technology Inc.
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|   Model LVCMOS_33_PM_HYST-ON_DIO_I
[Model]   LVCMOS_33_PM_HYST-ON_DIO_I
Model_type   Input
Vinl =   0.8
Vinh =   2.0
|   typ   min   max
C_comp   5.210e-12   5.210e-12   5.520e-12
[Model Spec]
Vinh+   1.733   1.654   1.811
Vinh-   1.733   1.654   1.811
Vinl+   1.568   1.496   1.639
Vinl-   1.568   1.496   1.639
[Temperature Range]  25C   100C   -40C
[Voltage Range]  3.3   3.135   3.465
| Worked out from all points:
|   GND clamp passes 1 mA (typ) near -1.86 V on its own axis
[GND Clamp]
| Voltage   I(typ)   I(min)   I(max)
-3.3V     -20.1mA    -18.21mA   -23.29mA
-1.624V   -532.6uA   -631.3uA   -587uA
-1.516V   -479.6uA   -498.3uA   -563.1uA
-1.408V   -452.4uA   -428.3uA   -542.3uA
-1.299V   -432.5uA   -390.6uA   -521.8uA
-1.083V   -397.1uA   -348.8uA   -481.6uA
-649.7mV  -333.9uA   -287.6uA   -406.7uA
-433.1mV  -311uA     -266.2uA   -380.2uA
3.094V    -17.38uA   -3.13uA    -36.54uA
3.3V      228.6pA    0A         -16.25uA
3.465V    0A         0A         231.1pA
6.6V      0A         0A         0A
[POWER Clamp]
| Voltage   I(typ)   I(min)   I(max)
-3.3V     281.4uA    249.3uA    335.8uA
-1.191V   110.1uA    96.03uA    134.8uA
-1.083V   101.2uA    88.04uA    129.8uA
-974.5mV  92.29uA    80.02uA    129.8uA
-758mV    88.73uA    66.26uA    129.8uA
-649.7mV  88.73uA    64.53uA    129.8uA
-541.4mV  88.73uA    64.53uA    112.6uA
-433.1mV  54.32uA    51.09uA    67.5uA
-324.8mV  28.05uA    27.17uA    32.88uA
-165mV    13.92uA    12.55uA    16.26uA
0V        0A         1.879uA    0A
6.6V      0A         0A         0A
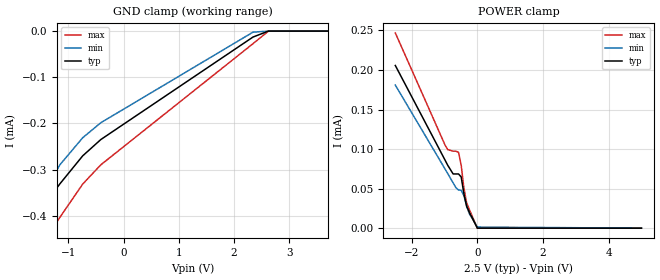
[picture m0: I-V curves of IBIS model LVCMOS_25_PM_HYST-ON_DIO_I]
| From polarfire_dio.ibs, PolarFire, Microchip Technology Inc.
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|   Model LVCMOS_25_PM_HYST-ON_DIO_I
[Model]   LVCMOS_25_PM_HYST-ON_DIO_I
Model_type   Input
Vinl =   0.7
Vinh =   1.7
|   typ   min   max
C_comp   5.210e-12   5.210e-12   5.520e-12
[Model Spec]
Vinh+   1.313   1.247   1.378
Vinh-   1.313   1.247   1.378
Vinl+   1.188   1.128   1.247
Vinl-   1.188   1.128   1.247
[Temperature Range]  25C   100C   -40C
[Voltage Range]  2.5   2.375   2.625
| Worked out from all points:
|   GND clamp passes 1 mA (typ) near -1.89 V on its own axis
[GND Clamp]
| Voltage   I(typ)   I(min)   I(max)
-2.5V     -7.363mA   -7.269mA   -7.846mA
-1.641V   -464.8uA   -585uA     -498.2uA
-1.559V   -416.1uA   -467uA     -478.9uA
-1.477V   -388.9uA   -394.3uA   -462.9uA
-1.395V   -371uA     -350uA     -447.6uA
-1.312V   -356.5uA   -322.4uA   -432.5uA
-1.148V   -330.1uA   -288.9uA   -402.5uA
-738.3mV  -270uA     -230.8uA   -331.1uA
-410.2mV  -234.7uA   -198.3uA   -289.4uA
2.344V    -12.87uA   -2.297uA   -27.23uA
2.625V    0A         0A         173.1pA
5V        0A         0A         0A
[POWER Clamp]
| Voltage   I(typ)   I(min)   I(max)
-2.5V     205.7uA    180.9uA    246.9uA
-984.4mV  86.05uA    74.8uA     105.1uA
-902.3mV  79.47uA    68.96uA    99.31uA
-738.3mV  68.54uA    57.24uA    97.39uA
-656.2mV  68.54uA    51.36uA    97.39uA
-574.2mV  68.54uA    48.22uA    95.95uA
-492.2mV  64.69uA    47.89uA    79.46uA
-410.2mV  43.48uA    41.11uA    50.52uA
-328.1mV  27.79uA    28.26uA    32.42uA
-246.1mV  20.33uA    18.38uA    23.88uA
0V        0A         1.379uA    0A
5V        0A         0A         0A
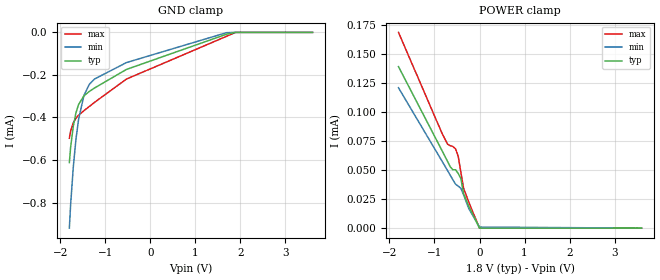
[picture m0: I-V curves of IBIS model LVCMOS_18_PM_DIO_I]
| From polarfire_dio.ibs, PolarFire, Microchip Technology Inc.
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|   Model LVCMOS_18_PM_DIO_I
[Model]   LVCMOS_18_PM_DIO_I
Model_type   Input
Vinl =   0.63
Vinh =   1.17
|   typ   min   max
C_comp   5.210e-12   5.210e-12   5.520e-12
[Temperature Range]  25C   100C   -40C
[Voltage Range]  1.8   1.71   1.89
[GND Clamp]
| Voltage   I(typ)   I(min)   I(max)
-1.8V     -612.2uA   -920.4uA   -497.6uA
-1.772V   -540.9uA   -811uA     -464uA
-1.713V   -441.8uA   -634.4uA   -425.4uA
-1.654V   -378.6uA   -503.4uA   -403.7uA
-1.595V   -339.1uA   -409.1uA   -389.6uA
-1.477V   -298.6uA   -297.1uA   -368.4uA
-1.358V   -277.8uA   -244.7uA   -348.6uA
-1.24V    -261.4uA   -219.2uA   -328.8uA
-531.6mV  -174.2uA   -142uA     -219.5uA
1.688V    -8.837uA   -1.554uA   -18.93uA
1.89V     0A         0A         169.1pA
3.6V      0A         0A         0A
[POWER Clamp]
| Voltage   I(typ)   I(min)   I(max)
-1.8V     139.1uA    120.9uA    168.6uA
-826.9mV  66.32uA    57.3uA     81.14uA
-708.7mV  57.34uA    49.46uA    72.31uA
-649.7mV  52.84uA    45.52uA    70.98uA
-590.6mV  50.26uA    41.58uA    70.29uA
-531.6mV  50.26uA    37.83uA    68.26uA
-472.5mV  47.02uA    36.14uA    61.72uA
-413.4mV  42.66uA    34.26uA    47.92uA
-354.4mV  29.72uA    28.64uA    34.42uA
-236.2mV  18.66uA    16.67uA    22.17uA
0V        0A         933.8nA    0A
3.6V      0A         0A         0A
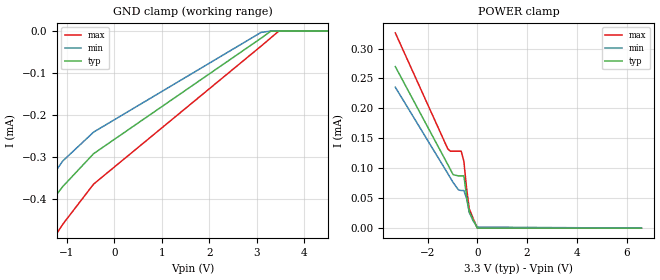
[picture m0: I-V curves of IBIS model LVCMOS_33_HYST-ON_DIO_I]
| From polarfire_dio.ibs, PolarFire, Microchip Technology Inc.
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|   Model LVCMOS_33_HYST-ON_DIO_I
[Model]   LVCMOS_33_HYST-ON_DIO_I
Model_type   Input
Vinl =   0.8
Vinh =   2.0
|   typ   min   max
C_comp   5.210e-12   5.210e-12   5.520e-12
[Model Spec]
Vinh+   1.733   1.654   1.811
Vinh-   1.733   1.654   1.811
Vinl+   1.568   1.496   1.639
Vinl-   1.568   1.496   1.639
[Temperature Range]  25C   100C   -40C
[Voltage Range]  3.3   3.135   3.465
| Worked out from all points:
|   GND clamp passes 1 mA (typ) near -1.87 V on its own axis
[GND Clamp]
| Voltage   I(typ)   I(min)   I(max)
-3.3V     -19.98mA   -18.06mA   -23.21mA
-1.732V   -613uA     -808.8uA   -601uA
-1.624V   -496.3uA   -571.9uA   -559.5uA
-1.516V   -445.7uA   -443.7uA   -537uA
-1.408V   -420.5uA   -378.2uA   -517.5uA
-1.299V   -402.6uA   -344.5uA   -498.3uA
-1.083V   -370.5uA   -309.6uA   -460.4uA
-433.1mV  -292.1uA   -240.7uA   -364.6uA
3.094V    -16.82uA   -2.989uA   -35.69uA
3.3V      228.4pA    0A         -15.88uA
3.465V    0A         0A         231.1pA
6.6V      0A         0A         0A
[POWER Clamp]
| Voltage   I(typ)   I(min)   I(max)
-3.3V     269.8uA    235.4uA    326.1uA
-1.191V   106.4uA    91.34uA    132.5uA
-1.083V   97.87uA    83.8uA     128.5uA
-974.5mV  89.31uA    76.25uA    128.5uA
-758mV    87.27uA    63.9uA     128.5uA
-649.7mV  87.27uA    62.86uA    128.5uA
-541.4mV  87.27uA    62.86uA    111.4uA
-433.1mV  53.21uA    49.65uA    66.59uA
-324.8mV  27.21uA    26.11uA    32.18uA
-165mV    13.48uA    12uA       15.9uA
0V        0A         1.795uA    0A
6.6V      0A         0A         0A
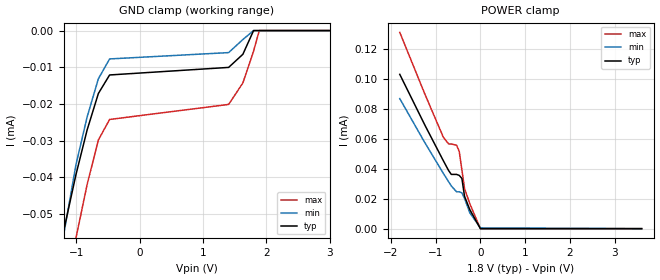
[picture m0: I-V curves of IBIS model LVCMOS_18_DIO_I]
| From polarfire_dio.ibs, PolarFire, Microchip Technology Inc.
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|   Model LVCMOS_18_DIO_I
[Model]   LVCMOS_18_DIO_I
Model_type   Input
Vinl =   0.63
Vinh =   1.17
|   typ   min   max
C_comp   5.210e-12   5.210e-12   5.520e-12
[Temperature Range]  25C   100C   -40C
[Voltage Range]  1.8   1.71   1.89
[GND Clamp]
| Voltage   I(typ)   I(min)   I(max)
-1.8V     -387.8uA   -753.4uA   -208.2uA
-1.299V   -63.12uA   -69.48uA   -83.18uA
-1.24V    -57.95uA   -59.85uA   -77.72uA
-1.004V   -39.29uA   -36.58uA   -56.57uA
-826.9mV  -27.05uA   -23.51uA   -41.92uA
-649.7mV  -17.14uA   -13.13uA   -29.82uA
-472.5mV  -12.1uA    -7.729uA   -24.23uA
1.406V    -10.04uA   -6.004uA   -20.13uA
1.631V    -6.466uA   -2.436uA   -14.28uA
1.8V      123.4pA    0A         -5.583uA
1.89V     0A         0A         124pA
3.6V      0A         0A         0A
[POWER Clamp]
| Voltage   I(typ)   I(min)   I(max)
-1.8V     103.3uA    87.05uA    131.4uA
-1.24V    69.33uA    57.53uA    90.1uA
-826.9mV  45.45uA    36.99uA    61.18uA
-708.7mV  38.86uA    31.37uA    56.68uA
-649.7mV  36.32uA    28.61uA    56.68uA
-531.6mV  36.32uA    24.67uA    55.88uA
-472.5mV  35.67uA    24.67uA    51.67uA
-413.4mV  33.62uA    24uA       39.39uA
-354.4mV  21.64uA    20.23uA    26.83uA
-236.2mV  12.71uA    10.6uA     16.68uA
0V        0A         486.2nA    0A
3.6V      0A         0A         0A
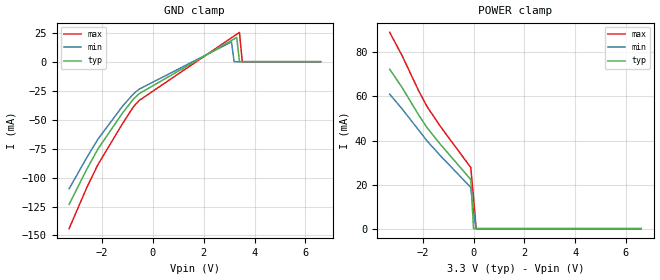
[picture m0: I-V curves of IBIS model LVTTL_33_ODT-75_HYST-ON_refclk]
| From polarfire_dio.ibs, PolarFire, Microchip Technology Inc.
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|   Model LVTTL_33_ODT-75_HYST-ON_refclk
[Model]   LVTTL_33_ODT-75_HYST-ON_refclk
Model_type   Input
Vinl =   0.8
Vinh =   2.0
|   typ   min   max
C_comp   5.210e-12   5.210e-12   5.520e-12
[Temperature Range]  25C   100C   -40C
[Voltage Range]  3.3   3.135   3.465
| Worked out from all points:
|   POWER clamp passes 1 mA (typ) near -0.00 V on its own axis
[GND Clamp]
| Voltage   I(typ)   I(min)   I(max)
-3.3V     -123.2mA   -109.7mA   -144.1mA
-2.599V   -92.62mA   -82.57mA   -108.4mA
-2.166V   -75.4mA    -66.93mA   -88.86mA
-1.191V   -44.06mA   -38.24mA   -53.25mA
-758mV    -32.03mA   -27.6mA    -38.64mA
-541.4mV  -27.59mA   -23.7mA    -33.48mA
3.094V    18.35mA    17.07mA    20.62mA
3.197V    19.64mA    0A         22.15mA
3.3V      20.93mA    0A         23.68mA
3.408V    0A         0A         25.28mA
3.517V    0A         0A         0A
6.6V      0A         0A         0A
[POWER Clamp]
| Voltage   I(typ)   I(min)   I(max)
-3.3V     72.33mA    61mA       89.06mA
-2.815V   64.08mA    54.38mA    78.57mA
-2.166V   51.69mA    44.81mA    62.68mA
-1.841V   45.97mA    39.97mA    55.62mA
-1.299V   38.16mA    33.02mA    46.29mA
-108.3mV  22.29mA    18.72mA    27.73mA
0V        0A         7.284mA    14.09mA
103.1mV   0A         0A         0A
6.6V      0A         0A         0A
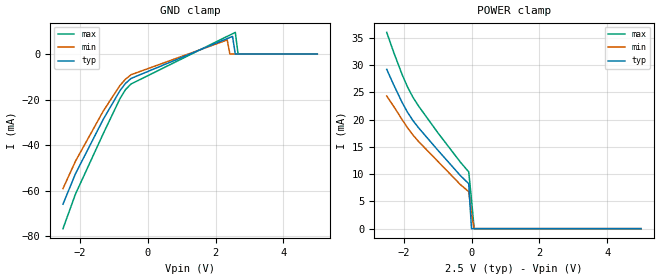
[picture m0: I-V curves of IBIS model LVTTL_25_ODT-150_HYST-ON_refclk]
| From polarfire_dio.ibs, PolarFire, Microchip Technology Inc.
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|   Model LVTTL_25_ODT-150_HYST-ON_refclk
[Model]   LVTTL_25_ODT-150_HYST-ON_refclk
Model_type   Input
Vinl =   0.8
Vinh =   2.0
|   typ   min   max
C_comp   5.210e-12   5.210e-12   5.520e-12
[Temperature Range]  25C   100C   -40C
[Voltage Range]  2.5   2.375   2.625
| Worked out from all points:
|   POWER clamp passes 1 mA (typ) near -0.01 V on its own axis
[GND Clamp]
| Voltage   I(typ)   I(min)   I(max)
-2.5V     -65.83mA   -58.98mA   -76.57mA
-2.133V   -52.53mA   -47.02mA   -61.45mA
-1.312V   -28.6mA    -24.98mA   -34.88mA
-820.3mV  -16.05mA   -13.78mA   -19.58mA
-656.2mV  -12.86mA   -11mA      -15.59mA
-492.2mV  -10.69mA   -9.063mA   -13.11mA
2.344V    6.801mA    6.194mA    7.761mA
2.422V    7.276mA    0A         8.331mA
2.5V      7.749mA    0A         8.901mA
2.582V    0A         0A         9.5mA
2.664V    0A         0A         0A
5V        0A         0A         0A
[POWER Clamp]
| Voltage   I(typ)   I(min)   I(max)
-2.5V     29.21mA    24.32mA    35.99mA
-2.297V   26.4mA     22.45mA    32.37mA
-2.051V   23.2mA     20.04mA    28.33mA
-1.887V   21.34mA    18.5mA     25.98mA
-1.723V   19.79mA    17.14mA    24.05mA
-1.559V   18.48mA    15.97mA    22.46mA
-984.4mV  14.33mA    12.29mA    17.52mA
-328.1mV  9.734mA    8.081mA    12.2mA
-82.03mV  8.246mA    6.783mA    10.41mA
0V        0A         2.64mA     5.289mA
78.12mV   0A         0A         0A
5V        0A         0A         0A
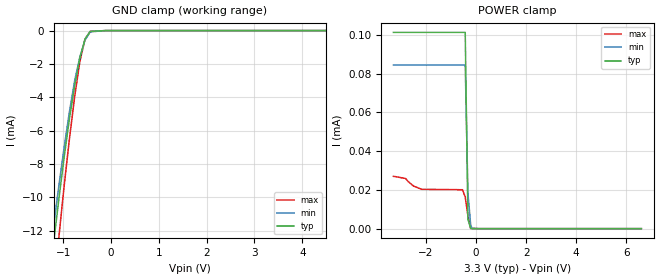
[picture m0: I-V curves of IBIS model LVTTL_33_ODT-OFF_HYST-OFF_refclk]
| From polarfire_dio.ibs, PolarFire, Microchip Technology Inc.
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|   Model LVTTL_33_ODT-OFF_HYST-OFF_refclk
[Model]   LVTTL_33_ODT-OFF_HYST-OFF_refclk
Model_type   Input
Vinl =   0.8
Vinh =   2.0
|   typ   min   max
C_comp   5.210e-12   5.210e-12   5.520e-12
[Temperature Range]  25C   100C   -40C
[Voltage Range]  3.3   3.135   3.465
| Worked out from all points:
|   GND clamp passes 1 mA (typ) near -0.59 V on its own axis
[GND Clamp]
| Voltage   I(typ)   I(min)   I(max)
-3.3V     -81.73mA   -75.27mA   -93.52mA
-1.408V   -18.01mA   -16.5mA    -21.72mA
-1.191V   -12.56mA   -11.55mA   -15.38mA
-1.083V   -9.973mA   -9.186mA   -12.23mA
-974.5mV  -7.519mA   -6.929mA   -9.214mA
-866.2mV  -5.259mA   -4.836mA   -6.455mA
-758mV    -3.292mA   -3.006mA   -3.951mA
-649.7mV  -1.65mA    -1.574mA   -1.856mA
-541.4mV  -510.1uA   -568.4uA   -505.8uA
-433.1mV  -46.69uA   -75.87uA   -45.55uA
-108.3mV  11nA       -4.164nA   -4.031nA
6.6V      0A         0A         0A
[POWER Clamp]
| Voltage   I(typ)   I(min)   I(max)
-3.3V     101.3uA    84.44uA    27.02uA
-2.815V   101.3uA    84.44uA    25.9uA
-2.707V   101.3uA    84.44uA    24.25uA
-2.49V    101.3uA    84.44uA    21.94uA
-2.166V   101.3uA    84.44uA    20.31uA
-541.4mV  101.3uA    84.44uA    20.09uA
-433.1mV  101.3uA    84.44uA    16.37uA
-324.8mV  4.863uA    18.34uA    6.499uA
-216.6mV  91.72nA    2.076uA    130.4nA
-165mV    12.82nA    167.8nA    130.4nA
103.1mV   0A         0A         0A
6.6V      0A         0A         0A
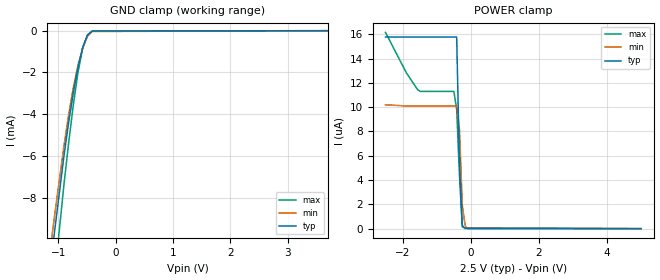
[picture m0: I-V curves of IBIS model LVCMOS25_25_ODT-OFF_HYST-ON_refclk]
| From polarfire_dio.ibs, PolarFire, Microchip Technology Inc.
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|   Model LVCMOS25_25_ODT-OFF_HYST-ON_refclk
[Model]   LVCMOS25_25_ODT-OFF_HYST-ON_refclk
Model_type   Input
Vinl =   0.7
Vinh =   1.7
|   typ   min   max
C_comp   5.210e-12   5.210e-12   5.520e-12
[Temperature Range]  25C   100C   -40C
[Voltage Range]  2.5   2.375   2.625
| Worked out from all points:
|   GND clamp passes 1 mA (typ) near -0.59 V on its own axis
[GND Clamp]
| Voltage   I(typ)   I(min)   I(max)
-2.5V     -50.62mA   -47.15mA   -57.43mA
-1.23V    -13.52mA   -12.43mA   -16.52mA
-1.148V   -11.52mA   -10.6mA    -14.11mA
-1.066V   -9.581mA   -8.827mA   -11.74mA
-902.3mV  -5.975mA   -5.502mA   -7.338mA
-820.3mV  -4.378mA   -4.012mA   -5.35mA
-738.3mV  -2.961mA   -2.707mA   -3.528mA
-656.2mV  -1.735mA   -1.644mA   -1.964mA
-574.2mV  -787.2uA   -824.8uA   -813.2uA
-492.2mV  -214.7uA   -270uA     -208.1uA
-410.2mV  -22.22uA   -41.6uA    -20.31uA
5V        0A         0A         0A
[POWER Clamp]
| Voltage   I(typ)   I(min)   I(max)
-2.5V     15.78uA    10.2uA     16.16uA
-1.887V   15.78uA    10.1uA     12.83uA
-1.559V   15.78uA    10.1uA     11.45uA
-1.477V   15.78uA    10.1uA     11.3uA
-492.2mV  15.78uA    10.1uA     11.3uA
-410.2mV  15.78uA    10.1uA     9.821uA
-328.1mV  5.28uA     8.134uA    4.392uA
-246.1mV  271.6nA    1.951uA    140.7nA
-164.1mV  11.86nA    303.9nA    64.96nA
-125mV    3.801nA    47.21nA    64.96nA
-82.03mV  3.801nA    23.39nA    64.96nA
5V        0A         0A         0A
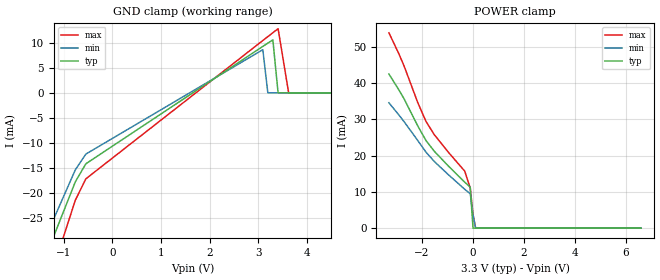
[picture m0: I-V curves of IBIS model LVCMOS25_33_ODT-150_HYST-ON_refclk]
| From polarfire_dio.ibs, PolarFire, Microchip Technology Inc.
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|   Model LVCMOS25_33_ODT-150_HYST-ON_refclk
[Model]   LVCMOS25_33_ODT-150_HYST-ON_refclk
Model_type   Input
Vinl =   0.7
Vinh =   1.7
|   typ   min   max
C_comp   5.210e-12   5.210e-12   5.520e-12
[Temperature Range]  25C   100C   -40C
[Voltage Range]  3.3   3.135   3.465
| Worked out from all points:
|   POWER clamp passes 1 mA (typ) near -0.01 V on its own axis
[GND Clamp]
| Voltage   I(typ)   I(min)   I(max)
-3.3V     -102.6mA   -92.6mA    -119mA
-1.624V   -40.72mA   -36.03mA   -48.75mA
-1.408V   -34.5mA    -30.4mA    -41.7mA
-1.191V   -28.42mA   -24.97mA   -34.49mA
-758mV    -17.78mA   -15.39mA   -21.46mA
-541.4mV  -14.18mA   -12.24mA   -17.19mA
3.094V    9.293mA    8.633mA    10.47mA
3.197V    9.947mA    0A         11.24mA
3.3V      10.6mA     0A         12.02mA
3.408V    0A         0A         12.83mA
3.625V    0A         0A         0A
6.6V      0A         0A         0A
[POWER Clamp]
| Voltage   I(typ)   I(min)   I(max)
-3.3V     42.45mA    34.53mA    53.78mA
-2.924V   38.24mA    31.3mA     48.24mA
-2.707V   35.65mA    29.35mA    44.69mA
-2.166V   28.12mA    24.12mA    34.54mA
-1.841V   24.08mA    20.89mA    29.34mA
-1.516V   21.16mA    18.34mA    25.71mA
-974.5mV  17.17mA    14.78mA    20.97mA
-324.8mV  12.66mA    10.71mA    15.71mA
-108.3mV  11.29mA    9.467mA    11.02mA
0V        0A         3.683mA    3.788mA
103.1mV   0A         0A         0A
6.6V      0A         0A         0A
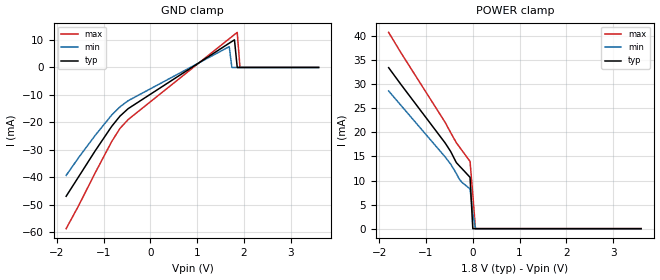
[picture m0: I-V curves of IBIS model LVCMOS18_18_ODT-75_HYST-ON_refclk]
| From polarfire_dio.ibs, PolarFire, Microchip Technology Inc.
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|   Model LVCMOS18_18_ODT-75_HYST-ON_refclk
[Model]   LVCMOS18_18_ODT-75_HYST-ON_refclk
Model_type   Input
Vinl =   0.63
Vinh =   1.17
|   typ   min   max
C_comp   5.210e-12   5.210e-12   5.520e-12
[Temperature Range]  25C   100C   -40C
[Voltage Range]  1.8   1.71   1.89
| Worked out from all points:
|   POWER clamp passes 1 mA (typ) near -0.01 V on its own axis
[GND Clamp]
| Voltage   I(typ)   I(min)   I(max)
-1.8V     -46.85mA   -39.27mA   -58.63mA
-1.536V   -39.83mA   -32.86mA   -50.35mA
-1.181V   -30.37mA   -24.75mA   -38.4mA
-826.9mV  -21.45mA   -17.33mA   -26.98mA
-649.7mV  -17.71mA   -14.34mA   -22.19mA
-472.5mV  -14.97mA   -12.08mA   -18.92mA
1.688V    8.831mA    7.574mA    10.45mA
1.744V    9.435mA    0A         11.2mA
1.8V      10.04mA    0A         11.96mA
1.859V    0A         0A         12.75mA
1.918V    0A         0A         0A
3.6V      0A         0A         0A
[POWER Clamp]
| Voltage   I(typ)   I(min)   I(max)
-1.8V     33.43mA    28.6mA     40.76mA
-1.536V   29.93mA    25.6mA     36.52mA
-590.6mV  17.78mA    14.88mA    22.06mA
-472.5mV  16.01mA    13.39mA    19.93mA
-354.4mV  13.75mA    11.49mA    17.87mA
-295.3mV  13.11mA    10.4mA     17.09mA
-236.2mV  12.51mA    9.647mA    16.31mA
-59.06mV  10.66mA    8.253mA    13.96mA
0V        0A         3.218mA    7.095mA
56.25mV   0A         0A         0A
3.6V      0A         0A         0A
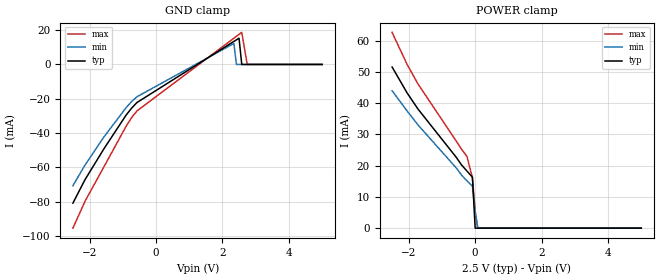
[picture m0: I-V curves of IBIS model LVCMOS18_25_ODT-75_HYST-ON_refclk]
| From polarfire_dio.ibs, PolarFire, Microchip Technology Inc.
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|   Model LVCMOS18_25_ODT-75_HYST-ON_refclk
[Model]   LVCMOS18_25_ODT-75_HYST-ON_refclk
Model_type   Input
Vinl =   0.63
Vinh =   1.17
|   typ   min   max
C_comp   5.210e-12   5.210e-12   5.520e-12
[Temperature Range]  25C   100C   -40C
[Voltage Range]  2.5   2.375   2.625
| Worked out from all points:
|   POWER clamp passes 1 mA (typ) near -0.01 V on its own axis
[GND Clamp]
| Voltage   I(typ)   I(min)   I(max)
-2.5V     -80.9mA    -70.73mA   -95.48mA
-2.133V   -67.09mA   -58.59mA   -79.7mA
-1.559V   -48.97mA   -42.11mA   -59.46mA
-902.3mV  -29.64mA   -25.28mA   -36.16mA
-738.3mV  -25.6mA    -21.75mA   -31.14mA
-574.2mV  -22.23mA   -18.87mA   -27.14mA
2.344V    13.44mA    12.26mA    15.29mA
2.422V    14.37mA    0A         16.42mA
2.5V      15.31mA    0A         17.54mA
2.582V    0A         0A         18.72mA
2.746V    0A         0A         0A
5V        0A         0A         0A
[POWER Clamp]
| Voltage   I(typ)   I(min)   I(max)
-2.5V     51.53mA    43.94mA    62.61mA
-2.051V   43.29mA    37.52mA    52.42mA
-1.723V   38.12mA    33.04mA    46.14mA
-574.2mV  22.72mA    19.31mA    27.91mA
-410.2mV  20.22mA    16.98mA    25.24mA
-246.1mV  18.25mA    15.1mA     22.88mA
-82.03mV  16.29mA    13.42mA    16.06mA
0V        0A         5.225mA    5.521mA
78.12mV   0A         0A         0A
5V        0A         0A         0A
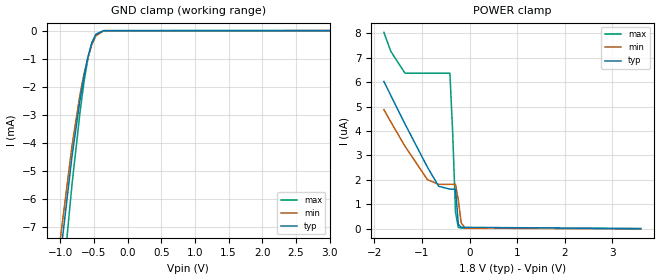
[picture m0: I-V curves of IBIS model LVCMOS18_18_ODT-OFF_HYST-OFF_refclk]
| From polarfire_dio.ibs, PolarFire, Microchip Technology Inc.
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|   Model LVCMOS18_18_ODT-OFF_HYST-OFF_refclk
[Model]   LVCMOS18_18_ODT-OFF_HYST-OFF_refclk
Model_type   Input
Vinl =   0.63
Vinh =   1.17
|   typ   min   max
C_comp   5.210e-12   5.210e-12   5.520e-12
[Temperature Range]  25C   100C   -40C
[Voltage Range]  1.8   1.71   1.89
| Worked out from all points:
|   GND clamp passes 1 mA (typ) near -0.60 V on its own axis
[GND Clamp]
| Voltage   I(typ)   I(min)   I(max)
-1.8V     -28.2mA    -26.04mA   -32.79mA
-1.417V   -18.23mA   -16.7mA    -21.95mA
-1.181V   -12.28mA   -11.3mA    -15.02mA
-1.004V   -8.136mA   -7.501mA   -9.957mA
-826.9mV  -4.479mA   -4.108mA   -5.483mA
-708.7mV  -2.483mA   -2.282mA   -2.92mA
-649.7mV  -1.641mA   -1.56mA    -1.85mA
-590.6mV  -946.2uA   -963uA     -999.9uA
-531.6mV  -438.1uA   -495.3uA   -430.8uA
-472.5mV  -137.8uA   -184.9uA   -134.8uA
-354.4mV  -2.91uA    -8.315uA   -1.748uA
3.6V      0A         0A         0A
[POWER Clamp]
| Voltage   I(typ)   I(min)   I(max)
-1.8V     6.025uA    4.872uA    8.035uA
-1.654V   5.448uA    4.366uA    7.255uA
-1.358V   4.291uA    3.378uA    6.364uA
-885.9mV  2.519uA    2.007uA    6.364uA
-649.7mV  1.735uA    1.814uA    6.364uA
-413.4mV  1.619uA    1.814uA    6.364uA
-354.4mV  1.619uA    1.814uA    3.905uA
-295.3mV  1.619uA    1.814uA    664.8nA
-236.2mV  181.9nA    1.173uA    50.48nA
-177.2mV  54.15nA    238.2nA    23.99nA
-90mV     54.15nA    15.2nA     23.99nA
3.6V      0A         0A         0A
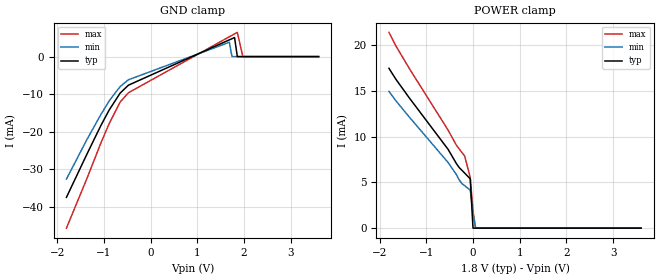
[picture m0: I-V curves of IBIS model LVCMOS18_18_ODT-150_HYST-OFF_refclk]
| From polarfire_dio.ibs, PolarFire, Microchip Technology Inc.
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|   Model LVCMOS18_18_ODT-150_HYST-OFF_refclk
[Model]   LVCMOS18_18_ODT-150_HYST-OFF_refclk
Model_type   Input
Vinl =   0.63
Vinh =   1.17
|   typ   min   max
C_comp   5.210e-12   5.210e-12   5.520e-12
[Temperature Range]  25C   100C   -40C
[Voltage Range]  1.8   1.71   1.89
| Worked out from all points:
|   POWER clamp passes 1 mA (typ) near -0.01 V on its own axis
[GND Clamp]
| Voltage   I(typ)   I(min)   I(max)
-1.8V     -37.55mA   -32.67mA   -45.76mA
-1.358V   -25.93mA   -22.05mA   -32.42mA
-1.063V   -18.41mA   -15.46mA   -23.07mA
-885.9mV  -14.26mA   -11.84mA   -17.91mA
-649.7mV  -9.731mA   -7.982mA   -12.11mA
-472.5mV  -7.621mA   -6.177mA   -9.637mA
1.688V    4.466mA    3.822mA    5.297mA
1.744V    4.771mA    0A         5.681mA
1.8V      5.074mA    0A         6.065mA
1.859V    0A         0A         6.467mA
1.977V    0A         0A         0A
3.6V      0A         0A         0A
[POWER Clamp]
| Voltage   I(typ)   I(min)   I(max)
-1.8V     17.49mA    14.96mA    21.42mA
-1.654V   16.31mA    13.95mA    19.96mA
-1.358V   14.21mA    12.12mA    17.42mA
-531.6mV  8.608mA    7.172mA    10.71mA
-354.4mV  7.053mA    5.853mA    9.061mA
-295.3mV  6.629mA    5.275mA    8.665mA
-236.2mV  6.324mA    4.864mA    8.27mA
-177.2mV  6.016mA    4.637mA    7.874mA
-59.06mV  5.391mA    4.164mA    5.537mA
0V        0A         1.624mA    1.903mA
56.25mV   0A         0A         0A
3.6V      0A         0A         0A
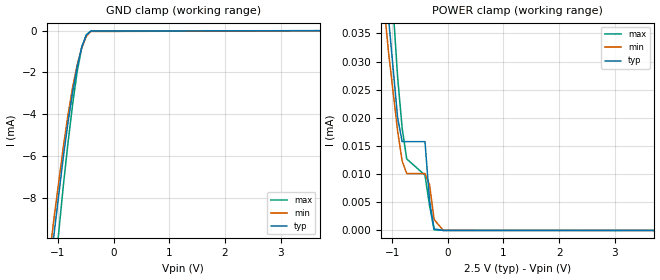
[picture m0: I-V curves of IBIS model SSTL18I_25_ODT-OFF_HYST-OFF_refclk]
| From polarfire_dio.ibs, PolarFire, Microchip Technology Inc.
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|   Model SSTL18I_25_ODT-OFF_HYST-OFF_refclk
[Model]   SSTL18I_25_ODT-OFF_HYST-OFF_refclk
Model_type   Input
Vinl =   0.775
Vinh =   1.025
|   typ   min   max
C_comp   5.210e-12   5.210e-12   5.520e-12
[Temperature Range]  25C   100C   -40C
[Voltage Range]  2.5   2.375   2.625
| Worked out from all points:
|   GND clamp passes 1 mA (typ) near -0.59 V on its own axis
[GND Clamp]
| Voltage   I(typ)   I(min)   I(max)
-2.5V     -50.62mA   -47.15mA   -57.43mA
-1.23V    -13.52mA   -12.43mA   -16.52mA
-1.148V   -11.52mA   -10.6mA    -14.11mA
-1.066V   -9.581mA   -8.827mA   -11.74mA
-902.3mV  -5.975mA   -5.502mA   -7.338mA
-820.3mV  -4.378mA   -4.012mA   -5.35mA
-738.3mV  -2.961mA   -2.707mA   -3.528mA
-656.2mV  -1.735mA   -1.644mA   -1.964mA
-574.2mV  -787.2uA   -824.8uA   -813.2uA
-492.2mV  -214.7uA   -270uA     -208.1uA
-410.2mV  -22.22uA   -41.6uA    -20.31uA
5V        0A         0A         0A
[POWER Clamp]
| Voltage   I(typ)   I(min)   I(max)
-2.5V     316.7uA    224.8uA    405.4uA
-1.312V   73.32uA    59.52uA    99.49uA
-1.148V   48.63uA    40.16uA    66.69uA
-1.066V   37.84uA    31.74uA    52.11uA
-902.3mV  20.05uA    17.67uA    27.31uA
-820.3mV  15.78uA    12.33uA    18.14uA
-738.3mV  15.78uA    10.1uA     12.71uA
-410.2mV  15.78uA    10.1uA     9.821uA
-328.1mV  5.283uA    8.134uA    4.392uA
-246.1mV  272.4nA    1.951uA    116nA
-82.03mV  9.588nA    24.05nA    13.03nA
5V        0A         0A         0A
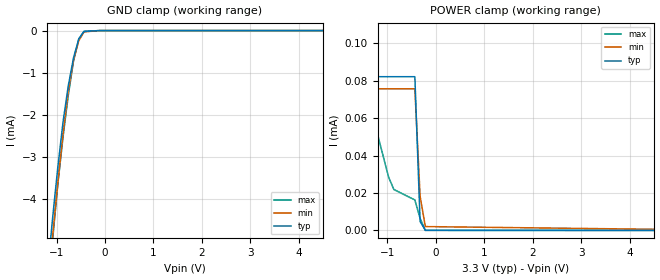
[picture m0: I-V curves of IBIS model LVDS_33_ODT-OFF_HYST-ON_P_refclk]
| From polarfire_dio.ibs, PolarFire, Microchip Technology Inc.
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|   Model LVDS_33_ODT-OFF_HYST-ON_P_refclk
[Model]   LVDS_33_ODT-OFF_HYST-ON_P_refclk
Model_type   Input
Vinl =   1.125
Vinh =   1.375
|   typ   min   max
C_comp   2.671e-12   2.671e-12   2.761e-12
[Temperature Range]  25C   100C   -40C
[Voltage Range]  3.3   3.135   3.465
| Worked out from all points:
|   GND clamp passes 1 mA (typ) near -0.71 V on its own axis
[GND Clamp]
| Voltage   I(typ)   I(min)   I(max)
-3.3V     -52.73mA   -49.44mA   -59.6mA
-1.191V   -5.764mA   -6.191mA   -6.42mA
-1.083V   -4.455mA   -4.874mA   -4.976mA
-974.5mV  -3.24mA    -3.609mA   -3.645mA
-866.2mV  -2.162mA   -2.435mA   -2.518mA
-758mV    -1.304mA   -1.429mA   -1.53mA
-649.7mV  -641.9uA   -701.3uA   -716.7uA
-541.4mV  -199uA     -240.8uA   -197.3uA
-433.1mV  -18.68uA   -31.08uA   -18.22uA
-108.3mV  -1.573nA   -2.534nA   -6.436nA
6.6V      0A         0A         0A
[POWER Clamp]
| Voltage   I(typ)   I(min)   I(max)
-3.3V     265.4uA    191.7uA    354.1uA
-2.057V   128.7uA    100.7uA    172.2uA
-1.841V   102.7uA    82.78uA    139uA
-1.732V   90.16uA    77.95uA    122.8uA
-1.516V   82.14uA    75.66uA    91.81uA
-1.191V   82.14uA    75.66uA    50.11uA
-974.5mV  82.14uA    75.66uA    28.44uA
-866.2mV  82.14uA    75.66uA    21.9uA
-433.1mV  82.14uA    75.66uA    16.31uA
-324.8mV  4.862uA    18.32uA    6.48uA
-216.6mV  91.87nA    2.076uA    58.59nA
6.6V      0A         0A         0A
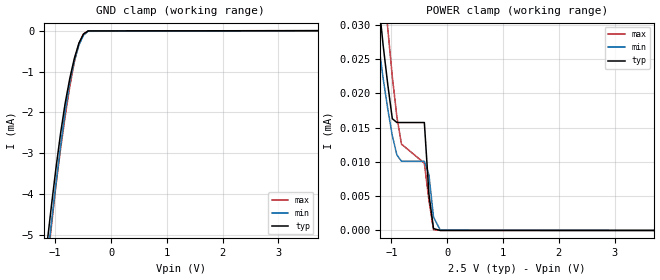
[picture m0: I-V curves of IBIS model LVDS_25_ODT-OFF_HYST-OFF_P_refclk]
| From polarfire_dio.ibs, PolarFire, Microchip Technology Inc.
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|   Model LVDS_25_ODT-OFF_HYST-OFF_P_refclk
[Model]   LVDS_25_ODT-OFF_HYST-OFF_P_refclk
Model_type   Input
Vinl =   1.125
Vinh =   1.375
|   typ   min   max
C_comp   2.671e-12   2.671e-12   2.761e-12
[Temperature Range]  25C   100C   -40C
[Voltage Range]  2.5   2.375   2.625
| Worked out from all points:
|   GND clamp passes 1 mA (typ) near -0.71 V on its own axis
[GND Clamp]
| Voltage   I(typ)   I(min)   I(max)
-2.5V     -29.4mA    -28.64mA   -32.16mA
-1.148V   -5.237mA   -5.665mA   -5.842mA
-1.066V   -4.263mA   -4.676mA   -4.763mA
-984.4mV  -3.345mA   -3.72mA    -3.757mA
-902.3mV  -2.5mA     -2.812mA   -2.875mA
-820.3mV  -1.769mA   -1.98mA    -2.082mA
-738.3mV  -1.169mA   -1.273mA   -1.366mA
-656.2mV  -676.7uA   -736.6uA   -759uA
-574.2mV  -306.4uA   -355.3uA   -315.8uA
-492.2mV  -84.67uA   -112.3uA   -81.93uA
-410.2mV  -8.927uA   -17.01uA   -8.161uA
5V        0A         0A         0A
[POWER Clamp]
| Voltage   I(typ)   I(min)   I(max)
-2.5V     163.6uA    113.2uA    216.7uA
-1.312V   39.97uA    32.33uA    54.48uA
-1.148V   26.95uA    22.14uA    37.14uA
-1.066V   21.3uA     17.74uA    29.47uA
-984.4mV  16.3uA     13.81uA    22.42uA
-902.3mV  15.74uA    11.02uA    16.55uA
-820.3mV  15.74uA    10.09uA    12.59uA
-410.2mV  15.74uA    10.09uA    9.815uA
-328.1mV  5.279uA    8.127uA    4.391uA
-246.1mV  271.6nA    1.951uA    118.3nA
-125mV    2.737nA    47.14nA    17.65nA
5V        0A         0A         0A
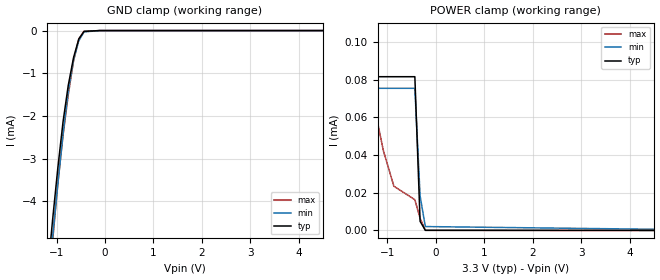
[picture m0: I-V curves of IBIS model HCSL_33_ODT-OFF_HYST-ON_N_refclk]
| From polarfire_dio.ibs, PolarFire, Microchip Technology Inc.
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|   Model HCSL_33_ODT-OFF_HYST-ON_N_refclk
[Model]   HCSL_33_ODT-OFF_HYST-ON_N_refclk
Model_type   Input
Vinl =   0.225
Vinh =   0.475
|   typ   min   max
C_comp   2.671e-12   2.671e-12   2.761e-12
[Temperature Range]  25C   100C   -40C
[Voltage Range]  3.3   3.135   3.465
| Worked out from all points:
|   GND clamp passes 1 mA (typ) near -0.71 V on its own axis
[GND Clamp]
| Voltage   I(typ)   I(min)   I(max)
-3.3V     -52.75mA   -49.47mA   -59.64mA
-1.191V   -5.758mA   -6.191mA   -6.408mA
-1.083V   -4.447mA   -4.872mA   -4.952mA
-974.5mV  -3.225mA   -3.606mA   -3.588mA
-866.2mV  -2.135mA   -2.429mA   -2.451mA
-758mV    -1.279mA   -1.419mA   -1.499mA
-649.7mV  -634uA     -693.7uA   -709uA
-541.4mV  -197.9uA   -239.4uA   -196.4uA
-433.1mV  -18.64uA   -31.03uA   -18.18uA
-108.3mV  -1.607nA   -2.598nA   -6.538nA
6.6V      0A         0A         0A
[POWER Clamp]
| Voltage   I(typ)   I(min)   I(max)
-3.3V     277.2uA    202.6uA    360.3uA
-2.057V   132.9uA    104.3uA    176.6uA
-1.841V   106.7uA    83.54uA    143.5uA
-1.732V   94.14uA    76.98uA    127.4uA
-1.624V   81.93uA    75.39uA    111.5uA
-1.516V   81.53uA    75.39uA    96.13uA
-1.083V   81.53uA    75.39uA    42.31uA
-866.2mV  81.53uA    75.39uA    23.47uA
-433.1mV  81.53uA    75.39uA    16.32uA
-324.8mV  4.861uA    18.31uA    6.48uA
-216.6mV  92.15nA    2.076uA    79.05nA
6.6V      0A         0A         0A
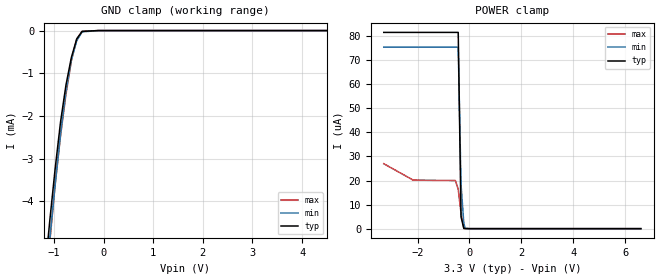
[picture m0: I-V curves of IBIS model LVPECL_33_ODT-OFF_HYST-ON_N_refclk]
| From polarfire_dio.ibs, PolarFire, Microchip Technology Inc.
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|   Model LVPECL_33_ODT-OFF_HYST-ON_N_refclk
[Model]   LVPECL_33_ODT-OFF_HYST-ON_N_refclk
Model_type   Input
Vinl =   1.525
Vinh =   1.775
|   typ   min   max
C_comp   2.671e-12   2.671e-12   2.761e-12
[Temperature Range]  25C   100C   -40C
[Voltage Range]  3.3   3.135   3.465
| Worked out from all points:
|   GND clamp passes 1 mA (typ) near -0.71 V on its own axis
[GND Clamp]
| Voltage   I(typ)   I(min)   I(max)
-3.3V     -52.75mA   -49.47mA   -59.64mA
-1.191V   -5.758mA   -6.191mA   -6.408mA
-1.083V   -4.447mA   -4.872mA   -4.952mA
-974.5mV  -3.225mA   -3.606mA   -3.588mA
-866.2mV  -2.135mA   -2.429mA   -2.451mA
-758mV    -1.279mA   -1.419mA   -1.499mA
-649.7mV  -634uA     -693.6uA   -708.9uA
-541.4mV  -197.9uA   -239.3uA   -196.4uA
-433.1mV  -18.63uA   -31.03uA   -18.17uA
-108.3mV  -1.589nA   -2.493nA   -6.818nA
6.6V      0A         0A         0A
[POWER Clamp]
| Voltage   I(typ)   I(min)   I(max)
-3.3V     81.53uA    75.39uA    26.98uA
-2.166V   81.53uA    75.39uA    20.16uA
-541.4mV  81.53uA    75.39uA    19.99uA
-433.1mV  81.53uA    75.39uA    16.32uA
-324.8mV  4.861uA    18.31uA    6.48uA
-216.6mV  97.48nA    2.076uA    69.42nA
-165mV    36.23nA    167.7nA    41.8nA
0V        0A         2.61nA     0A
6.6V      0A         0A         0A
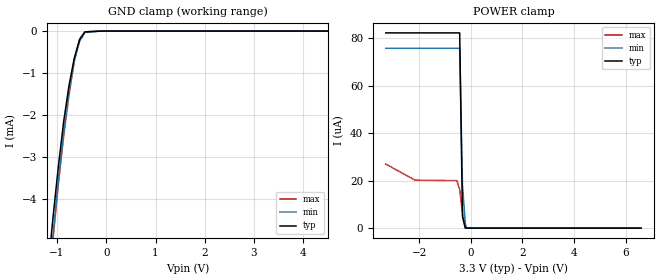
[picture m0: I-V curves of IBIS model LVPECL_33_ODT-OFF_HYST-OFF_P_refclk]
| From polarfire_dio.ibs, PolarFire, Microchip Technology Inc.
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|   Model LVPECL_33_ODT-OFF_HYST-OFF_P_refclk
[Model]   LVPECL_33_ODT-OFF_HYST-OFF_P_refclk
Model_type   Input
Vinl =   1.525
Vinh =   1.775
|   typ   min   max
C_comp   2.671e-12   2.671e-12   2.761e-12
[Temperature Range]  25C   100C   -40C
[Voltage Range]  3.3   3.135   3.465
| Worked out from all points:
|   GND clamp passes 1 mA (typ) near -0.71 V on its own axis
[GND Clamp]
| Voltage   I(typ)   I(min)   I(max)
-3.3V     -52.73mA   -49.44mA   -59.6mA
-1.191V   -5.763mA   -6.191mA   -6.42mA
-1.083V   -4.455mA   -4.873mA   -4.976mA
-974.5mV  -3.24mA    -3.609mA   -3.645mA
-866.2mV  -2.162mA   -2.435mA   -2.518mA
-758mV    -1.304mA   -1.429mA   -1.529mA
-649.7mV  -641.8uA   -701.3uA   -716.5uA
-541.4mV  -199uA     -240.7uA   -197.2uA
-433.1mV  -18.67uA   -31.07uA   -18.2uA
-108.3mV  -1.573nA   -2.557nA   -5.856nA
6.6V      0A         0A         0A
[POWER Clamp]
| Voltage   I(typ)   I(min)   I(max)
-3.3V     82.14uA    75.66uA    26.97uA
-2.166V   82.14uA    75.66uA    20.2uA
-541.4mV  82.14uA    75.66uA    19.98uA
-433.1mV  82.14uA    75.66uA    16.31uA
-324.8mV  4.862uA    18.32uA    6.481uA
-216.6mV  91.71nA    2.091uA    51.88nA
-165mV    31.9nA     197.2nA    6.499nA
103.1mV   0A         0A         0A
6.6V      0A         0A         0A
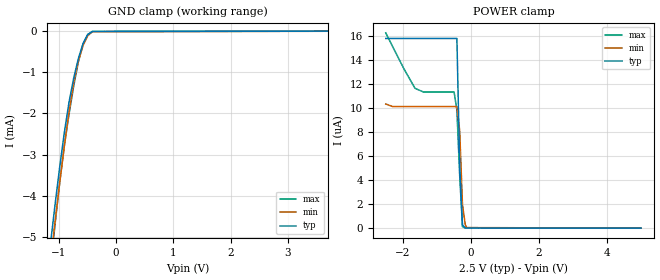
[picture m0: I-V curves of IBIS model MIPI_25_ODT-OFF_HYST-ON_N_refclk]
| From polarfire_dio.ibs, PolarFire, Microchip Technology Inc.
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|   Model MIPI_25_ODT-OFF_HYST-ON_N_refclk
[Model]   MIPI_25_ODT-OFF_HYST-ON_N_refclk
Model_type   Input
Vinl =   1.125
Vinh =   1.375
|   typ   min   max
C_comp   2.671e-12   2.671e-12   2.761e-12
[Temperature Range]  25C   100C   -40C
[Voltage Range]  2.5   2.375   2.625
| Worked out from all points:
|   GND clamp passes 1 mA (typ) near -0.71 V on its own axis
[GND Clamp]
| Voltage   I(typ)   I(min)   I(max)
-2.5V     -29.41mA   -28.65mA   -32.17mA
-1.148V   -5.23mA    -5.664mA   -5.826mA
-1.066V   -4.254mA   -4.675mA   -4.737mA
-984.4mV  -3.331mA   -3.717mA   -3.705mA
-902.3mV  -2.478mA   -2.807mA   -2.8mA
-820.3mV  -1.738mA   -1.973mA   -2.031mA
-738.3mV  -1.148mA   -1.262mA   -1.341mA
-656.2mV  -667.7uA   -728.4uA   -750.3uA
-574.2mV  -304.1uA   -352.5uA   -314uA
-492.2mV  -84.33uA   -111.9uA   -81.65uA
-410.2mV  -8.903uA   -16.98uA   -8.141uA
5V        0A         0A         0A
[POWER Clamp]
| Voltage   I(typ)   I(min)   I(max)
-2.5V     15.76uA    10.31uA    16.22uA
-2.297V   15.76uA    10.1uA     15.08uA
-1.969V   15.76uA    10.1uA     13.25uA
-1.641V   15.76uA    10.1uA     11.62uA
-1.395V   15.76uA    10.1uA     11.31uA
-492.2mV  15.76uA    10.1uA     11.31uA
-410.2mV  15.76uA    10.1uA     9.823uA
-328.1mV  5.278uA    8.13uA     4.39uA
-246.1mV  271.6nA    1.95uA     119.3nA
-164.1mV  14.77nA    303.7nA    20.04nA
-125mV    14.77nA    47.11nA    20.04nA
5V        0A         0A         0A
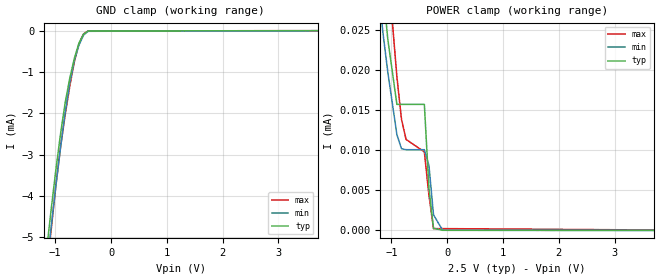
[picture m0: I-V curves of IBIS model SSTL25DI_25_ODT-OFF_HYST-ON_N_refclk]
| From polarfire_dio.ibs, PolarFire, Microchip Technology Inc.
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|   Model SSTL25DI_25_ODT-OFF_HYST-ON_N_refclk
[Model]   SSTL25DI_25_ODT-OFF_HYST-ON_N_refclk
Model_type   Input
Vinl =   1.1
Vinh =   1.4
|   typ   min   max
C_comp   2.671e-12   2.671e-12   2.761e-12
[Temperature Range]  25C   100C   -40C
[Voltage Range]  2.5   2.375   2.625
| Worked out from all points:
|   GND clamp passes 1 mA (typ) near -0.71 V on its own axis
[GND Clamp]
| Voltage   I(typ)   I(min)   I(max)
-2.5V     -29.41mA   -28.65mA   -32.17mA
-1.148V   -5.231mA   -5.664mA   -5.827mA
-1.066V   -4.254mA   -4.675mA   -4.737mA
-984.4mV  -3.331mA   -3.717mA   -3.705mA
-902.3mV  -2.478mA   -2.807mA   -2.8mA
-820.3mV  -1.738mA   -1.973mA   -2.031mA
-738.3mV  -1.148mA   -1.262mA   -1.341mA
-656.2mV  -667.7uA   -728.5uA   -750.4uA
-574.2mV  -304.1uA   -352.5uA   -314.1uA
-492.2mV  -84.35uA   -112uA     -81.68uA
-410.2mV  -8.907uA   -16.99uA   -8.147uA
5V        0A         0A         0A
[POWER Clamp]
| Voltage   I(typ)   I(min)   I(max)
-2.5V     172.7uA    122.1uA    221.5uA
-1.312V   43.36uA    35.03uA    58.78uA
-1.148V   29.9uA     24.47uA    41uA
-1.066V   23.96uA    19.84uA    33.02uA
-902.3mV  15.76uA    11.98uA    19.22uA
-820.3mV  15.76uA    10.22uA    13.92uA
-738.3mV  15.76uA    10.1uA     11.38uA
-410.2mV  15.76uA    10.1uA     9.823uA
-328.1mV  5.279uA    8.13uA     4.402uA
-246.1mV  271.7nA    1.95uA     233.5nA
-82.03mV  29.34nA    23.29nA    233.5nA
5V        0A         0A         0A
